VERSION 5.7 ;
  NOWIREEXTENSIONATPIN ON ;
  DIVIDERCHAR "/" ;
  BUSBITCHARS "[]" ;
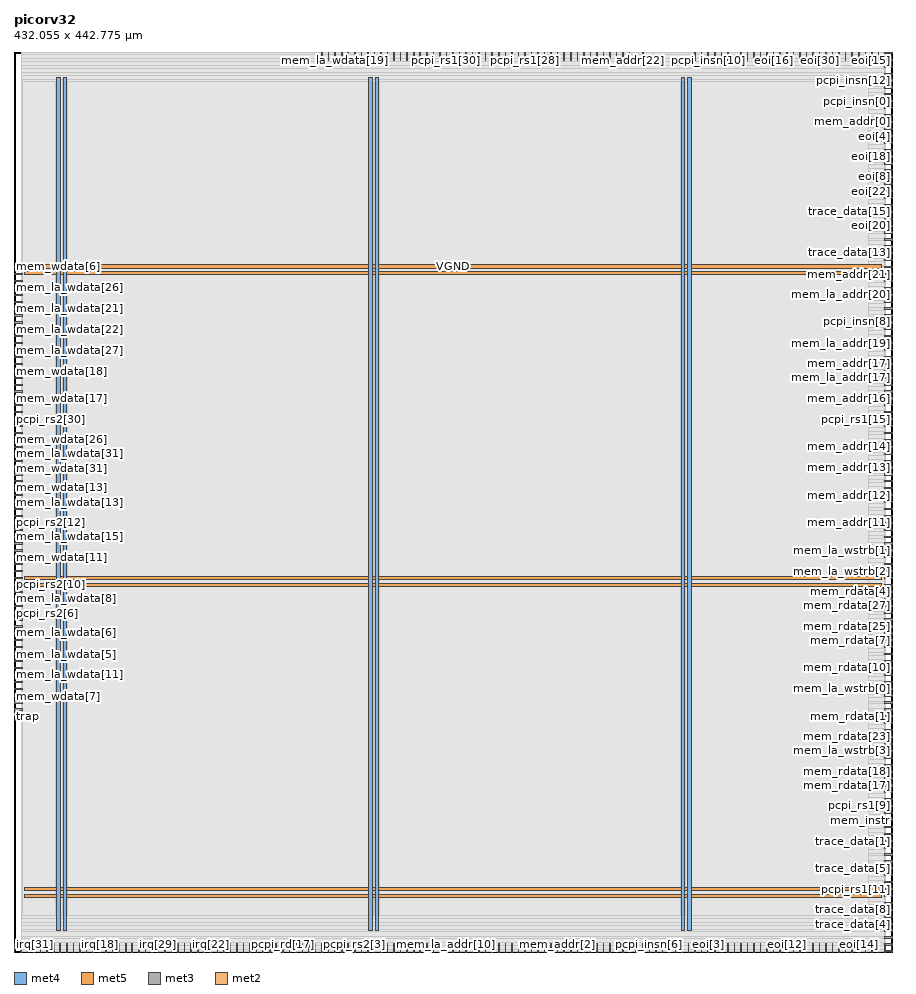
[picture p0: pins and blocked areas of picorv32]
MACRO picorv32
  CLASS BLOCK ;
  FOREIGN picorv32 ;
  ORIGIN 0.000 0.000 ;
  SIZE 432.055 BY 442.775 ;
  PIN VGND
    DIRECTION INOUT ;
    USE GROUND ;
    PORT
      LAYER met4 ;
        RECT 24.340 10.640 25.940 430.000 ;
    END
    PORT
      LAYER met4 ;
        RECT 177.940 10.640 179.540 430.000 ;
    END
    PORT
      LAYER met4 ;
        RECT 331.540 10.640 333.140 430.000 ;
    END
    PORT
      LAYER met5 ;
        RECT 5.280 30.030 426.660 31.630 ;
    END
    PORT
      LAYER met5 ;
        RECT 5.280 183.210 426.660 184.810 ;
    END
    PORT
      LAYER met5 ;
        RECT 5.280 336.390 426.660 337.990 ;
    END
  END VGND
  PIN VPWR
    DIRECTION INOUT ;
    USE POWER ;
    PORT
      LAYER met4 ;
        RECT 21.040 10.640 22.640 430.000 ;
    END
    PORT
      LAYER met4 ;
        RECT 174.640 10.640 176.240 430.000 ;
    END
    PORT
      LAYER met4 ;
        RECT 328.240 10.640 329.840 430.000 ;
    END
    PORT
      LAYER met5 ;
        RECT 5.280 26.730 426.660 28.330 ;
    END
    PORT
      LAYER met5 ;
        RECT 5.280 179.910 426.660 181.510 ;
    END
    PORT
      LAYER met5 ;
        RECT 5.280 333.090 426.660 334.690 ;
    END
  END VPWR
  PIN clk
    DIRECTION INPUT ;
    USE SIGNAL ;
    ANTENNAGATEAREA 0.990000 ;
    PORT
      LAYER met3 ;
        RECT 428.055 0.040 432.055 0.640 ;
    END
  END clk
  PIN eoi[0]
    DIRECTION OUTPUT ;
    USE SIGNAL ;
    PORT
      LAYER met2 ;
        RECT 283.450 0.000 283.730 4.000 ;
    END
  END eoi[0]
  PIN eoi[10]
    DIRECTION OUTPUT ;
    USE SIGNAL ;
    PORT
      LAYER met3 ;
        RECT 428.055 44.240 432.055 44.840 ;
    END
  END eoi[10]
  PIN eoi[11]
    DIRECTION OUTPUT ;
    USE SIGNAL ;
    PORT
      LAYER met3 ;
        RECT 428.055 3.440 432.055 4.040 ;
    END
  END eoi[11]
  PIN eoi[12]
    DIRECTION OUTPUT ;
    USE SIGNAL ;
    PORT
      LAYER met2 ;
        RECT 380.050 0.000 380.330 4.000 ;
    END
  END eoi[12]
  PIN eoi[13]
    DIRECTION OUTPUT ;
    USE SIGNAL ;
    PORT
      LAYER met3 ;
        RECT 428.055 353.640 432.055 354.240 ;
    END
  END eoi[13]
  PIN eoi[14]
    DIRECTION OUTPUT ;
    USE SIGNAL ;
    PORT
      LAYER met2 ;
        RECT 415.470 0.000 415.750 4.000 ;
    END
  END eoi[14]
  PIN eoi[15]
    DIRECTION OUTPUT ;
    USE SIGNAL ;
    PORT
      LAYER met2 ;
        RECT 428.350 438.775 428.630 442.775 ;
    END
  END eoi[15]
  PIN eoi[16]
    DIRECTION OUTPUT ;
    USE SIGNAL ;
    PORT
      LAYER met2 ;
        RECT 373.610 438.775 373.890 442.775 ;
    END
  END eoi[16]
  PIN eoi[17]
    DIRECTION OUTPUT ;
    USE SIGNAL ;
    PORT
      LAYER met3 ;
        RECT 428.055 363.840 432.055 364.440 ;
    END
  END eoi[17]
  PIN eoi[18]
    DIRECTION OUTPUT ;
    USE SIGNAL ;
    PORT
      LAYER met3 ;
        RECT 428.055 391.040 432.055 391.640 ;
    END
  END eoi[18]
  PIN eoi[19]
    DIRECTION OUTPUT ;
    USE SIGNAL ;
    PORT
      LAYER met3 ;
        RECT 428.055 421.640 432.055 422.240 ;
    END
  END eoi[19]
  PIN eoi[1]
    DIRECTION OUTPUT ;
    USE SIGNAL ;
    PORT
      LAYER met2 ;
        RECT 392.930 438.775 393.210 442.775 ;
    END
  END eoi[1]
  PIN eoi[20]
    DIRECTION OUTPUT ;
    USE SIGNAL ;
    PORT
      LAYER met3 ;
        RECT 428.055 357.040 432.055 357.640 ;
    END
  END eoi[20]
  PIN eoi[21]
    DIRECTION OUTPUT ;
    USE SIGNAL ;
    PORT
      LAYER met2 ;
        RECT 383.270 438.775 383.550 442.775 ;
    END
  END eoi[21]
  PIN eoi[22]
    DIRECTION OUTPUT ;
    USE SIGNAL ;
    PORT
      LAYER met3 ;
        RECT 428.055 374.040 432.055 374.640 ;
    END
  END eoi[22]
  PIN eoi[23]
    DIRECTION OUTPUT ;
    USE SIGNAL ;
    PORT
      LAYER met2 ;
        RECT 425.130 438.775 425.410 442.775 ;
    END
  END eoi[23]
  PIN eoi[24]
    DIRECTION OUTPUT ;
    USE SIGNAL ;
    PORT
      LAYER met3 ;
        RECT 428.055 51.040 432.055 51.640 ;
    END
  END eoi[24]
  PIN eoi[25]
    DIRECTION OUTPUT ;
    USE SIGNAL ;
    PORT
      LAYER met2 ;
        RECT 363.950 438.775 364.230 442.775 ;
    END
  END eoi[25]
  PIN eoi[26]
    DIRECTION OUTPUT ;
    USE SIGNAL ;
    PORT
      LAYER met2 ;
        RECT 415.470 438.775 415.750 442.775 ;
    END
  END eoi[26]
  PIN eoi[27]
    DIRECTION OUTPUT ;
    USE SIGNAL ;
    PORT
      LAYER met2 ;
        RECT 344.630 0.000 344.910 4.000 ;
    END
  END eoi[27]
  PIN eoi[28]
    DIRECTION OUTPUT ;
    USE SIGNAL ;
    PORT
      LAYER met2 ;
        RECT 418.690 438.775 418.970 442.775 ;
    END
  END eoi[28]
  PIN eoi[29]
    DIRECTION OUTPUT ;
    USE SIGNAL ;
    PORT
      LAYER met2 ;
        RECT 373.610 0.000 373.890 4.000 ;
    END
  END eoi[29]
  PIN eoi[2]
    DIRECTION OUTPUT ;
    USE SIGNAL ;
    PORT
      LAYER met2 ;
        RECT 402.590 438.775 402.870 442.775 ;
    END
  END eoi[2]
  PIN eoi[30]
    DIRECTION OUTPUT ;
    USE SIGNAL ;
    PORT
      LAYER met2 ;
        RECT 396.150 438.775 396.430 442.775 ;
    END
  END eoi[30]
  PIN eoi[31]
    DIRECTION OUTPUT ;
    USE SIGNAL ;
    PORT
      LAYER met2 ;
        RECT 370.390 438.775 370.670 442.775 ;
    END
  END eoi[31]
  PIN eoi[3]
    DIRECTION OUTPUT ;
    USE SIGNAL ;
    PORT
      LAYER met2 ;
        RECT 341.410 0.000 341.690 4.000 ;
    END
  END eoi[3]
  PIN eoi[4]
    DIRECTION OUTPUT ;
    USE SIGNAL ;
    PORT
      LAYER met3 ;
        RECT 428.055 404.640 432.055 405.240 ;
    END
  END eoi[4]
  PIN eoi[5]
    DIRECTION OUTPUT ;
    USE SIGNAL ;
    PORT
      LAYER met2 ;
        RECT 357.510 438.775 357.790 442.775 ;
    END
  END eoi[5]
  PIN eoi[6]
    DIRECTION OUTPUT ;
    USE SIGNAL ;
    PORT
      LAYER met3 ;
        RECT 428.055 23.840 432.055 24.440 ;
    END
  END eoi[6]
  PIN eoi[7]
    DIRECTION OUTPUT ;
    USE SIGNAL ;
    PORT
      LAYER met3 ;
        RECT 428.055 336.640 432.055 337.240 ;
    END
  END eoi[7]
  PIN eoi[8]
    DIRECTION OUTPUT ;
    USE SIGNAL ;
    PORT
      LAYER met3 ;
        RECT 428.055 377.440 432.055 378.040 ;
    END
  END eoi[8]
  PIN eoi[9]
    DIRECTION OUTPUT ;
    USE SIGNAL ;
    PORT
      LAYER met2 ;
        RECT 360.730 438.775 361.010 442.775 ;
    END
  END eoi[9]
  PIN irq[0]
    DIRECTION INPUT ;
    USE SIGNAL ;
    PORT
      LAYER met2 ;
        RECT 431.570 0.000 431.850 4.000 ;
    END
  END irq[0]
  PIN irq[10]
    DIRECTION INPUT ;
    USE SIGNAL ;
    PORT
      LAYER met2 ;
        RECT 116.010 0.000 116.290 4.000 ;
    END
  END irq[10]
  PIN irq[11]
    DIRECTION INPUT ;
    USE SIGNAL ;
    PORT
      LAYER met2 ;
        RECT 80.590 0.000 80.870 4.000 ;
    END
  END irq[11]
  PIN irq[12]
    DIRECTION INPUT ;
    USE SIGNAL ;
    PORT
      LAYER met2 ;
        RECT 74.150 0.000 74.430 4.000 ;
    END
  END irq[12]
  PIN irq[13]
    DIRECTION INPUT ;
    USE SIGNAL ;
    PORT
      LAYER met2 ;
        RECT 45.170 0.000 45.450 4.000 ;
    END
  END irq[13]
  PIN irq[14]
    DIRECTION INPUT ;
    USE SIGNAL ;
    PORT
      LAYER met2 ;
        RECT 64.490 0.000 64.770 4.000 ;
    END
  END irq[14]
  PIN irq[15]
    DIRECTION INPUT ;
    USE SIGNAL ;
    PORT
      LAYER met2 ;
        RECT 61.270 0.000 61.550 4.000 ;
    END
  END irq[15]
  PIN irq[16]
    DIRECTION INPUT ;
    USE SIGNAL ;
    PORT
      LAYER met2 ;
        RECT 138.550 0.000 138.830 4.000 ;
    END
  END irq[16]
  PIN irq[17]
    DIRECTION INPUT ;
    USE SIGNAL ;
    PORT
      LAYER met2 ;
        RECT 51.610 0.000 51.890 4.000 ;
    END
  END irq[17]
  PIN irq[18]
    DIRECTION INPUT ;
    USE SIGNAL ;
    PORT
      LAYER met2 ;
        RECT 41.950 0.000 42.230 4.000 ;
    END
  END irq[18]
  PIN irq[19]
    DIRECTION INPUT ;
    USE SIGNAL ;
    PORT
      LAYER met2 ;
        RECT 315.650 0.000 315.930 4.000 ;
    END
  END irq[19]
  PIN irq[1]
    DIRECTION INPUT ;
    USE SIGNAL ;
    PORT
      LAYER met2 ;
        RECT 135.330 0.000 135.610 4.000 ;
    END
  END irq[1]
  PIN irq[20]
    DIRECTION INPUT ;
    USE SIGNAL ;
    PORT
      LAYER met2 ;
        RECT 67.710 0.000 67.990 4.000 ;
    END
  END irq[20]
  PIN irq[21]
    DIRECTION INPUT ;
    USE SIGNAL ;
    PORT
      LAYER met2 ;
        RECT 22.630 0.000 22.910 4.000 ;
    END
  END irq[21]
  PIN irq[22]
    DIRECTION INPUT ;
    USE SIGNAL ;
    PORT
      LAYER met2 ;
        RECT 96.690 0.000 96.970 4.000 ;
    END
  END irq[22]
  PIN irq[23]
    DIRECTION INPUT ;
    USE SIGNAL ;
    PORT
      LAYER met2 ;
        RECT 77.370 0.000 77.650 4.000 ;
    END
  END irq[23]
  PIN irq[24]
    DIRECTION INPUT ;
    USE SIGNAL ;
    PORT
      LAYER met2 ;
        RECT 54.830 0.000 55.110 4.000 ;
    END
  END irq[24]
  PIN irq[25]
    DIRECTION INPUT ;
    USE SIGNAL ;
    PORT
      LAYER met2 ;
        RECT 421.910 0.000 422.190 4.000 ;
    END
  END irq[25]
  PIN irq[26]
    DIRECTION INPUT ;
    USE SIGNAL ;
    PORT
      LAYER met2 ;
        RECT 87.030 0.000 87.310 4.000 ;
    END
  END irq[26]
  PIN irq[27]
    DIRECTION INPUT ;
    USE SIGNAL ;
    PORT
      LAYER met2 ;
        RECT 119.230 0.000 119.510 4.000 ;
    END
  END irq[27]
  PIN irq[28]
    DIRECTION INPUT ;
    USE SIGNAL ;
    PORT
      LAYER met2 ;
        RECT 103.130 0.000 103.410 4.000 ;
    END
  END irq[28]
  PIN irq[29]
    DIRECTION INPUT ;
    USE SIGNAL ;
    PORT
      LAYER met2 ;
        RECT 70.930 0.000 71.210 4.000 ;
    END
  END irq[29]
  PIN irq[2]
    DIRECTION INPUT ;
    USE SIGNAL ;
    PORT
      LAYER met2 ;
        RECT 90.250 0.000 90.530 4.000 ;
    END
  END irq[2]
  PIN irq[30]
    DIRECTION INPUT ;
    USE SIGNAL ;
    PORT
      LAYER met2 ;
        RECT 289.890 0.000 290.170 4.000 ;
    END
  END irq[30]
  PIN irq[31]
    DIRECTION INPUT ;
    USE SIGNAL ;
    PORT
      LAYER met2 ;
        RECT 0.090 0.000 0.370 4.000 ;
    END
  END irq[31]
  PIN irq[3]
    DIRECTION INPUT ;
    USE SIGNAL ;
    PORT
      LAYER met2 ;
        RECT 409.030 0.000 409.310 4.000 ;
    END
  END irq[3]
  PIN irq[4]
    DIRECTION INPUT ;
    USE SIGNAL ;
    PORT
      LAYER met2 ;
        RECT 122.450 0.000 122.730 4.000 ;
    END
  END irq[4]
  PIN irq[5]
    DIRECTION INPUT ;
    USE SIGNAL ;
    PORT
      LAYER met2 ;
        RECT 106.350 0.000 106.630 4.000 ;
    END
  END irq[5]
  PIN irq[6]
    DIRECTION INPUT ;
    USE SIGNAL ;
    PORT
      LAYER met2 ;
        RECT 144.990 0.000 145.270 4.000 ;
    END
  END irq[6]
  PIN irq[7]
    DIRECTION INPUT ;
    USE SIGNAL ;
    PORT
      LAYER met2 ;
        RECT 112.790 0.000 113.070 4.000 ;
    END
  END irq[7]
  PIN irq[8]
    DIRECTION INPUT ;
    USE SIGNAL ;
    PORT
      LAYER met2 ;
        RECT 99.910 0.000 100.190 4.000 ;
    END
  END irq[8]
  PIN irq[9]
    DIRECTION INPUT ;
    USE SIGNAL ;
    PORT
      LAYER met2 ;
        RECT 93.470 0.000 93.750 4.000 ;
    END
  END irq[9]
  PIN mem_addr[0]
    DIRECTION OUTPUT ;
    USE SIGNAL ;
    PORT
      LAYER met3 ;
        RECT 428.055 408.040 432.055 408.640 ;
    END
  END mem_addr[0]
  PIN mem_addr[10]
    DIRECTION OUTPUT ;
    USE SIGNAL ;
    ANTENNADIFFAREA 0.340600 ;
    PORT
      LAYER met2 ;
        RECT 222.270 0.000 222.550 4.000 ;
    END
  END mem_addr[10]
  PIN mem_addr[11]
    DIRECTION OUTPUT ;
    USE SIGNAL ;
    ANTENNADIFFAREA 0.340600 ;
    PORT
      LAYER met3 ;
        RECT 428.055 210.840 432.055 211.440 ;
    END
  END mem_addr[11]
  PIN mem_addr[12]
    DIRECTION OUTPUT ;
    USE SIGNAL ;
    ANTENNADIFFAREA 0.340600 ;
    PORT
      LAYER met3 ;
        RECT 428.055 224.440 432.055 225.040 ;
    END
  END mem_addr[12]
  PIN mem_addr[13]
    DIRECTION OUTPUT ;
    USE SIGNAL ;
    ANTENNADIFFAREA 0.340600 ;
    PORT
      LAYER met3 ;
        RECT 428.055 238.040 432.055 238.640 ;
    END
  END mem_addr[13]
  PIN mem_addr[14]
    DIRECTION OUTPUT ;
    USE SIGNAL ;
    ANTENNADIFFAREA 0.340600 ;
    PORT
      LAYER met3 ;
        RECT 428.055 244.840 432.055 245.440 ;
    END
  END mem_addr[14]
  PIN mem_addr[15]
    DIRECTION OUTPUT ;
    USE SIGNAL ;
    ANTENNADIFFAREA 0.340600 ;
    PORT
      LAYER met3 ;
        RECT 428.055 261.840 432.055 262.440 ;
    END
  END mem_addr[15]
  PIN mem_addr[16]
    DIRECTION OUTPUT ;
    USE SIGNAL ;
    ANTENNADIFFAREA 0.340600 ;
    PORT
      LAYER met3 ;
        RECT 428.055 272.040 432.055 272.640 ;
    END
  END mem_addr[16]
  PIN mem_addr[17]
    DIRECTION OUTPUT ;
    USE SIGNAL ;
    ANTENNADIFFAREA 0.340600 ;
    PORT
      LAYER met3 ;
        RECT 428.055 285.640 432.055 286.240 ;
    END
  END mem_addr[17]
  PIN mem_addr[18]
    DIRECTION OUTPUT ;
    USE SIGNAL ;
    ANTENNADIFFAREA 0.340600 ;
    PORT
      LAYER met3 ;
        RECT 428.055 292.440 432.055 293.040 ;
    END
  END mem_addr[18]
  PIN mem_addr[19]
    DIRECTION OUTPUT ;
    USE SIGNAL ;
    ANTENNADIFFAREA 0.340600 ;
    PORT
      LAYER met3 ;
        RECT 428.055 295.840 432.055 296.440 ;
    END
  END mem_addr[19]
  PIN mem_addr[1]
    DIRECTION OUTPUT ;
    USE SIGNAL ;
    PORT
      LAYER met2 ;
        RECT 309.210 0.000 309.490 4.000 ;
    END
  END mem_addr[1]
  PIN mem_addr[20]
    DIRECTION OUTPUT ;
    USE SIGNAL ;
    ANTENNADIFFAREA 0.340600 ;
    PORT
      LAYER met3 ;
        RECT 428.055 329.840 432.055 330.440 ;
    END
  END mem_addr[20]
  PIN mem_addr[21]
    DIRECTION OUTPUT ;
    USE SIGNAL ;
    ANTENNADIFFAREA 0.340600 ;
    PORT
      LAYER met3 ;
        RECT 428.055 333.240 432.055 333.840 ;
    END
  END mem_addr[21]
  PIN mem_addr[22]
    DIRECTION OUTPUT ;
    USE SIGNAL ;
    ANTENNADIFFAREA 0.340600 ;
    PORT
      LAYER met2 ;
        RECT 299.550 438.775 299.830 442.775 ;
    END
  END mem_addr[22]
  PIN mem_addr[23]
    DIRECTION OUTPUT ;
    USE SIGNAL ;
    ANTENNADIFFAREA 0.340600 ;
    PORT
      LAYER met2 ;
        RECT 286.670 438.775 286.950 442.775 ;
    END
  END mem_addr[23]
  PIN mem_addr[24]
    DIRECTION OUTPUT ;
    USE SIGNAL ;
    ANTENNADIFFAREA 0.340600 ;
    PORT
      LAYER met2 ;
        RECT 277.010 438.775 277.290 442.775 ;
    END
  END mem_addr[24]
  PIN mem_addr[25]
    DIRECTION OUTPUT ;
    USE SIGNAL ;
    ANTENNADIFFAREA 0.340600 ;
    PORT
      LAYER met2 ;
        RECT 260.910 438.775 261.190 442.775 ;
    END
  END mem_addr[25]
  PIN mem_addr[26]
    DIRECTION OUTPUT ;
    USE SIGNAL ;
    ANTENNADIFFAREA 0.340600 ;
    PORT
      LAYER met2 ;
        RECT 257.690 438.775 257.970 442.775 ;
    END
  END mem_addr[26]
  PIN mem_addr[27]
    DIRECTION OUTPUT ;
    USE SIGNAL ;
    ANTENNADIFFAREA 0.340600 ;
    PORT
      LAYER met2 ;
        RECT 235.150 438.775 235.430 442.775 ;
    END
  END mem_addr[27]
  PIN mem_addr[28]
    DIRECTION OUTPUT ;
    USE SIGNAL ;
    ANTENNADIFFAREA 0.340600 ;
    PORT
      LAYER met2 ;
        RECT 222.270 438.775 222.550 442.775 ;
    END
  END mem_addr[28]
  PIN mem_addr[29]
    DIRECTION OUTPUT ;
    USE SIGNAL ;
    ANTENNADIFFAREA 0.340600 ;
    PORT
      LAYER met2 ;
        RECT 270.570 438.775 270.850 442.775 ;
    END
  END mem_addr[29]
  PIN mem_addr[2]
    DIRECTION OUTPUT ;
    USE SIGNAL ;
    ANTENNADIFFAREA 0.340600 ;
    PORT
      LAYER met2 ;
        RECT 267.350 0.000 267.630 4.000 ;
    END
  END mem_addr[2]
  PIN mem_addr[30]
    DIRECTION OUTPUT ;
    USE SIGNAL ;
    ANTENNADIFFAREA 0.340600 ;
    PORT
      LAYER met2 ;
        RECT 231.930 438.775 232.210 442.775 ;
    END
  END mem_addr[30]
  PIN mem_addr[31]
    DIRECTION OUTPUT ;
    USE SIGNAL ;
    ANTENNADIFFAREA 0.340600 ;
    PORT
      LAYER met2 ;
        RECT 244.810 438.775 245.090 442.775 ;
    END
  END mem_addr[31]
  PIN mem_addr[3]
    DIRECTION OUTPUT ;
    USE SIGNAL ;
    ANTENNADIFFAREA 0.340600 ;
    PORT
      LAYER met2 ;
        RECT 296.330 0.000 296.610 4.000 ;
    END
  END mem_addr[3]
  PIN mem_addr[4]
    DIRECTION OUTPUT ;
    USE SIGNAL ;
    ANTENNADIFFAREA 0.340600 ;
    PORT
      LAYER met2 ;
        RECT 251.250 0.000 251.530 4.000 ;
    END
  END mem_addr[4]
  PIN mem_addr[5]
    DIRECTION OUTPUT ;
    USE SIGNAL ;
    ANTENNADIFFAREA 0.340600 ;
    PORT
      LAYER met2 ;
        RECT 209.390 0.000 209.670 4.000 ;
    END
  END mem_addr[5]
  PIN mem_addr[6]
    DIRECTION OUTPUT ;
    USE SIGNAL ;
    ANTENNADIFFAREA 0.340600 ;
    PORT
      LAYER met2 ;
        RECT 238.370 0.000 238.650 4.000 ;
    END
  END mem_addr[6]
  PIN mem_addr[7]
    DIRECTION OUTPUT ;
    USE SIGNAL ;
    ANTENNADIFFAREA 0.340600 ;
    PORT
      LAYER met2 ;
        RECT 225.490 0.000 225.770 4.000 ;
    END
  END mem_addr[7]
  PIN mem_addr[8]
    DIRECTION OUTPUT ;
    USE SIGNAL ;
    ANTENNADIFFAREA 0.340600 ;
    PORT
      LAYER met2 ;
        RECT 228.710 0.000 228.990 4.000 ;
    END
  END mem_addr[8]
  PIN mem_addr[9]
    DIRECTION OUTPUT ;
    USE SIGNAL ;
    ANTENNADIFFAREA 0.340600 ;
    PORT
      LAYER met2 ;
        RECT 219.050 0.000 219.330 4.000 ;
    END
  END mem_addr[9]
  PIN mem_instr
    DIRECTION OUTPUT ;
    USE SIGNAL ;
    ANTENNADIFFAREA 0.340600 ;
    PORT
      LAYER met3 ;
        RECT 428.055 64.640 432.055 65.240 ;
    END
  END mem_instr
  PIN mem_la_addr[0]
    DIRECTION OUTPUT ;
    USE SIGNAL ;
    PORT
      LAYER met2 ;
        RECT 331.750 0.000 332.030 4.000 ;
    END
  END mem_la_addr[0]
  PIN mem_la_addr[10]
    DIRECTION OUTPUT ;
    USE SIGNAL ;
    ANTENNADIFFAREA 0.340600 ;
    PORT
      LAYER met2 ;
        RECT 212.610 0.000 212.890 4.000 ;
    END
  END mem_la_addr[10]
  PIN mem_la_addr[11]
    DIRECTION OUTPUT ;
    USE SIGNAL ;
    ANTENNADIFFAREA 0.340600 ;
    PORT
      LAYER met3 ;
        RECT 428.055 13.640 432.055 14.240 ;
    END
  END mem_la_addr[11]
  PIN mem_la_addr[12]
    DIRECTION OUTPUT ;
    USE SIGNAL ;
    ANTENNADIFFAREA 0.340600 ;
    PORT
      LAYER met3 ;
        RECT 428.055 221.040 432.055 221.640 ;
    END
  END mem_la_addr[12]
  PIN mem_la_addr[13]
    DIRECTION OUTPUT ;
    USE SIGNAL ;
    ANTENNADIFFAREA 0.340600 ;
    PORT
      LAYER met3 ;
        RECT 428.055 234.640 432.055 235.240 ;
    END
  END mem_la_addr[13]
  PIN mem_la_addr[14]
    DIRECTION OUTPUT ;
    USE SIGNAL ;
    ANTENNADIFFAREA 0.340600 ;
    PORT
      LAYER met3 ;
        RECT 428.055 241.440 432.055 242.040 ;
    END
  END mem_la_addr[14]
  PIN mem_la_addr[15]
    DIRECTION OUTPUT ;
    USE SIGNAL ;
    ANTENNADIFFAREA 0.340600 ;
    PORT
      LAYER met3 ;
        RECT 428.055 255.040 432.055 255.640 ;
    END
  END mem_la_addr[15]
  PIN mem_la_addr[16]
    DIRECTION OUTPUT ;
    USE SIGNAL ;
    ANTENNADIFFAREA 0.340600 ;
    PORT
      LAYER met3 ;
        RECT 428.055 268.640 432.055 269.240 ;
    END
  END mem_la_addr[16]
  PIN mem_la_addr[17]
    DIRECTION OUTPUT ;
    USE SIGNAL ;
    ANTENNADIFFAREA 0.340600 ;
    PORT
      LAYER met3 ;
        RECT 428.055 282.240 432.055 282.840 ;
    END
  END mem_la_addr[17]
  PIN mem_la_addr[18]
    DIRECTION OUTPUT ;
    USE SIGNAL ;
    ANTENNADIFFAREA 0.340600 ;
    PORT
      LAYER met3 ;
        RECT 428.055 302.640 432.055 303.240 ;
    END
  END mem_la_addr[18]
  PIN mem_la_addr[19]
    DIRECTION OUTPUT ;
    USE SIGNAL ;
    ANTENNADIFFAREA 0.340600 ;
    PORT
      LAYER met3 ;
        RECT 428.055 299.240 432.055 299.840 ;
    END
  END mem_la_addr[19]
  PIN mem_la_addr[1]
    DIRECTION OUTPUT ;
    USE SIGNAL ;
    PORT
      LAYER met3 ;
        RECT 428.055 47.640 432.055 48.240 ;
    END
  END mem_la_addr[1]
  PIN mem_la_addr[20]
    DIRECTION OUTPUT ;
    USE SIGNAL ;
    ANTENNADIFFAREA 0.340600 ;
    PORT
      LAYER met3 ;
        RECT 428.055 323.040 432.055 323.640 ;
    END
  END mem_la_addr[20]
  PIN mem_la_addr[21]
    DIRECTION OUTPUT ;
    USE SIGNAL ;
    ANTENNADIFFAREA 0.340600 ;
    PORT
      LAYER met3 ;
        RECT 428.055 309.440 432.055 310.040 ;
    END
  END mem_la_addr[21]
  PIN mem_la_addr[22]
    DIRECTION OUTPUT ;
    USE SIGNAL ;
    ANTENNADIFFAREA 0.340600 ;
    PORT
      LAYER met2 ;
        RECT 296.330 438.775 296.610 442.775 ;
    END
  END mem_la_addr[22]
  PIN mem_la_addr[23]
    DIRECTION OUTPUT ;
    USE SIGNAL ;
    ANTENNADIFFAREA 0.340600 ;
    PORT
      LAYER met2 ;
        RECT 283.450 438.775 283.730 442.775 ;
    END
  END mem_la_addr[23]
  PIN mem_la_addr[24]
    DIRECTION OUTPUT ;
    USE SIGNAL ;
    ANTENNADIFFAREA 0.340600 ;
    PORT
      LAYER met2 ;
        RECT 273.790 438.775 274.070 442.775 ;
    END
  END mem_la_addr[24]
  PIN mem_la_addr[25]
    DIRECTION OUTPUT ;
    USE SIGNAL ;
    ANTENNADIFFAREA 0.340600 ;
    PORT
      LAYER met2 ;
        RECT 264.130 438.775 264.410 442.775 ;
    END
  END mem_la_addr[25]
  PIN mem_la_addr[26]
    DIRECTION OUTPUT ;
    USE SIGNAL ;
    ANTENNADIFFAREA 0.340600 ;
    PORT
      LAYER met2 ;
        RECT 254.470 438.775 254.750 442.775 ;
    END
  END mem_la_addr[26]
  PIN mem_la_addr[27]
    DIRECTION OUTPUT ;
    USE SIGNAL ;
    ANTENNADIFFAREA 0.340600 ;
    PORT
      LAYER met2 ;
        RECT 238.370 438.775 238.650 442.775 ;
    END
  END mem_la_addr[27]
  PIN mem_la_addr[28]
    DIRECTION OUTPUT ;
    USE SIGNAL ;
    ANTENNADIFFAREA 0.340600 ;
    PORT
      LAYER met2 ;
        RECT 225.490 438.775 225.770 442.775 ;
    END
  END mem_la_addr[28]
  PIN mem_la_addr[29]
    DIRECTION OUTPUT ;
    USE SIGNAL ;
    ANTENNADIFFAREA 0.340600 ;
    PORT
      LAYER met2 ;
        RECT 267.350 438.775 267.630 442.775 ;
    END
  END mem_la_addr[29]
  PIN mem_la_addr[2]
    DIRECTION OUTPUT ;
    USE SIGNAL ;
    ANTENNADIFFAREA 0.340600 ;
    PORT
      LAYER met2 ;
        RECT 270.570 0.000 270.850 4.000 ;
    END
  END mem_la_addr[2]
  PIN mem_la_addr[30]
    DIRECTION OUTPUT ;
    USE SIGNAL ;
    ANTENNADIFFAREA 0.340600 ;
    PORT
      LAYER met2 ;
        RECT 228.710 438.775 228.990 442.775 ;
    END
  END mem_la_addr[30]
  PIN mem_la_addr[31]
    DIRECTION OUTPUT ;
    USE SIGNAL ;
    ANTENNADIFFAREA 0.340600 ;
    PORT
      LAYER met2 ;
        RECT 241.590 438.775 241.870 442.775 ;
    END
  END mem_la_addr[31]
  PIN mem_la_addr[3]
    DIRECTION OUTPUT ;
    USE SIGNAL ;
    ANTENNADIFFAREA 0.340600 ;
    PORT
      LAYER met2 ;
        RECT 293.110 0.000 293.390 4.000 ;
    END
  END mem_la_addr[3]
  PIN mem_la_addr[4]
    DIRECTION OUTPUT ;
    USE SIGNAL ;
    ANTENNADIFFAREA 0.340600 ;
    PORT
      LAYER met2 ;
        RECT 235.150 0.000 235.430 4.000 ;
    END
  END mem_la_addr[4]
  PIN mem_la_addr[5]
    DIRECTION OUTPUT ;
    USE SIGNAL ;
    ANTENNADIFFAREA 0.340600 ;
    PORT
      LAYER met2 ;
        RECT 231.930 0.000 232.210 4.000 ;
    END
  END mem_la_addr[5]
  PIN mem_la_addr[6]
    DIRECTION OUTPUT ;
    USE SIGNAL ;
    ANTENNADIFFAREA 0.340600 ;
    PORT
      LAYER met2 ;
        RECT 241.590 0.000 241.870 4.000 ;
    END
  END mem_la_addr[6]
  PIN mem_la_addr[7]
    DIRECTION OUTPUT ;
    USE SIGNAL ;
    ANTENNADIFFAREA 0.340600 ;
    PORT
      LAYER met2 ;
        RECT 244.810 0.000 245.090 4.000 ;
    END
  END mem_la_addr[7]
  PIN mem_la_addr[8]
    DIRECTION OUTPUT ;
    USE SIGNAL ;
    ANTENNADIFFAREA 0.340600 ;
    PORT
      LAYER met2 ;
        RECT 248.030 0.000 248.310 4.000 ;
    END
  END mem_la_addr[8]
  PIN mem_la_addr[9]
    DIRECTION OUTPUT ;
    USE SIGNAL ;
    ANTENNADIFFAREA 0.340600 ;
    PORT
      LAYER met2 ;
        RECT 215.830 0.000 216.110 4.000 ;
    END
  END mem_la_addr[9]
  PIN mem_la_read
    DIRECTION OUTPUT ;
    USE SIGNAL ;
    ANTENNADIFFAREA 0.340600 ;
    PORT
      LAYER met3 ;
        RECT 428.055 122.440 432.055 123.040 ;
    END
  END mem_la_read
  PIN mem_la_wdata[0]
    DIRECTION OUTPUT ;
    USE SIGNAL ;
    ANTENNADIFFAREA 0.340600 ;
    PORT
      LAYER met2 ;
        RECT 206.170 0.000 206.450 4.000 ;
    END
  END mem_la_wdata[0]
  PIN mem_la_wdata[10]
    DIRECTION OUTPUT ;
    USE SIGNAL ;
    ANTENNADIFFAREA 0.340600 ;
    PORT
      LAYER met3 ;
        RECT 0.000 122.440 4.000 123.040 ;
    END
  END mem_la_wdata[10]
  PIN mem_la_wdata[11]
    DIRECTION OUTPUT ;
    USE SIGNAL ;
    ANTENNADIFFAREA 0.340600 ;
    PORT
      LAYER met3 ;
        RECT 0.000 136.040 4.000 136.640 ;
    END
  END mem_la_wdata[11]
  PIN mem_la_wdata[12]
    DIRECTION OUTPUT ;
    USE SIGNAL ;
    ANTENNADIFFAREA 0.340600 ;
    PORT
      LAYER met3 ;
        RECT 0.000 166.640 4.000 167.240 ;
    END
  END mem_la_wdata[12]
  PIN mem_la_wdata[13]
    DIRECTION OUTPUT ;
    USE SIGNAL ;
    ANTENNADIFFAREA 0.340600 ;
    PORT
      LAYER met3 ;
        RECT 0.000 221.040 4.000 221.640 ;
    END
  END mem_la_wdata[13]
  PIN mem_la_wdata[14]
    DIRECTION OUTPUT ;
    USE SIGNAL ;
    ANTENNADIFFAREA 0.340600 ;
    PORT
      LAYER met3 ;
        RECT 0.000 217.640 4.000 218.240 ;
    END
  END mem_la_wdata[14]
  PIN mem_la_wdata[15]
    DIRECTION OUTPUT ;
    USE SIGNAL ;
    ANTENNADIFFAREA 0.340600 ;
    PORT
      LAYER met3 ;
        RECT 0.000 204.040 4.000 204.640 ;
    END
  END mem_la_wdata[15]
  PIN mem_la_wdata[16]
    DIRECTION OUTPUT ;
    USE SIGNAL ;
    ANTENNADIFFAREA 0.340600 ;
    PORT
      LAYER met2 ;
        RECT 186.850 438.775 187.130 442.775 ;
    END
  END mem_la_wdata[16]
  PIN mem_la_wdata[17]
    DIRECTION OUTPUT ;
    USE SIGNAL ;
    ANTENNADIFFAREA 0.340600 ;
    PORT
      LAYER met3 ;
        RECT 0.000 336.640 4.000 337.240 ;
    END
  END mem_la_wdata[17]
  PIN mem_la_wdata[18]
    DIRECTION OUTPUT ;
    USE SIGNAL ;
    ANTENNADIFFAREA 0.340600 ;
    PORT
      LAYER met3 ;
        RECT 0.000 295.840 4.000 296.440 ;
    END
  END mem_la_wdata[18]
  PIN mem_la_wdata[19]
    DIRECTION OUTPUT ;
    USE SIGNAL ;
    ANTENNADIFFAREA 0.340600 ;
    PORT
      LAYER met2 ;
        RECT 157.870 438.775 158.150 442.775 ;
    END
  END mem_la_wdata[19]
  PIN mem_la_wdata[1]
    DIRECTION OUTPUT ;
    USE SIGNAL ;
    ANTENNADIFFAREA 0.340600 ;
    PORT
      LAYER met2 ;
        RECT 180.410 0.000 180.690 4.000 ;
    END
  END mem_la_wdata[1]
  PIN mem_la_wdata[20]
    DIRECTION OUTPUT ;
    USE SIGNAL ;
    ANTENNADIFFAREA 0.340600 ;
    PORT
      LAYER met2 ;
        RECT 202.950 438.775 203.230 442.775 ;
    END
  END mem_la_wdata[20]
  PIN mem_la_wdata[21]
    DIRECTION OUTPUT ;
    USE SIGNAL ;
    ANTENNADIFFAREA 0.340600 ;
    PORT
      LAYER met3 ;
        RECT 0.000 316.240 4.000 316.840 ;
    END
  END mem_la_wdata[21]
  PIN mem_la_wdata[22]
    DIRECTION OUTPUT ;
    USE SIGNAL ;
    ANTENNADIFFAREA 0.340600 ;
    PORT
      LAYER met3 ;
        RECT 0.000 306.040 4.000 306.640 ;
    END
  END mem_la_wdata[22]
  PIN mem_la_wdata[23]
    DIRECTION OUTPUT ;
    USE SIGNAL ;
    ANTENNADIFFAREA 0.340600 ;
    PORT
      LAYER met3 ;
        RECT 0.000 251.640 4.000 252.240 ;
    END
  END mem_la_wdata[23]
  PIN mem_la_wdata[24]
    DIRECTION OUTPUT ;
    USE SIGNAL ;
    ANTENNADIFFAREA 0.340600 ;
    PORT
      LAYER met2 ;
        RECT 164.310 438.775 164.590 442.775 ;
    END
  END mem_la_wdata[24]
  PIN mem_la_wdata[25]
    DIRECTION OUTPUT ;
    USE SIGNAL ;
    ANTENNADIFFAREA 0.340600 ;
    PORT
      LAYER met3 ;
        RECT 0.000 285.640 4.000 286.240 ;
    END
  END mem_la_wdata[25]
  PIN mem_la_wdata[26]
    DIRECTION OUTPUT ;
    USE SIGNAL ;
    ANTENNADIFFAREA 0.340600 ;
    PORT
      LAYER met3 ;
        RECT 0.000 323.040 4.000 323.640 ;
    END
  END mem_la_wdata[26]
  PIN mem_la_wdata[27]
    DIRECTION OUTPUT ;
    USE SIGNAL ;
    ANTENNADIFFAREA 0.340600 ;
    PORT
      LAYER met3 ;
        RECT 0.000 299.240 4.000 299.840 ;
    END
  END mem_la_wdata[27]
  PIN mem_la_wdata[28]
    DIRECTION OUTPUT ;
    USE SIGNAL ;
    ANTENNADIFFAREA 0.340600 ;
    PORT
      LAYER met3 ;
        RECT 0.000 275.440 4.000 276.040 ;
    END
  END mem_la_wdata[28]
  PIN mem_la_wdata[29]
    DIRECTION OUTPUT ;
    USE SIGNAL ;
    ANTENNADIFFAREA 0.340600 ;
    PORT
      LAYER met3 ;
        RECT 0.000 268.640 4.000 269.240 ;
    END
  END mem_la_wdata[29]
  PIN mem_la_wdata[2]
    DIRECTION OUTPUT ;
    USE SIGNAL ;
    ANTENNADIFFAREA 0.340600 ;
    PORT
      LAYER met2 ;
        RECT 199.730 0.000 200.010 4.000 ;
    END
  END mem_la_wdata[2]
  PIN mem_la_wdata[30]
    DIRECTION OUTPUT ;
    USE SIGNAL ;
    ANTENNADIFFAREA 0.340600 ;
    PORT
      LAYER met3 ;
        RECT 0.000 329.840 4.000 330.440 ;
    END
  END mem_la_wdata[30]
  PIN mem_la_wdata[31]
    DIRECTION OUTPUT ;
    USE SIGNAL ;
    ANTENNADIFFAREA 0.340600 ;
    PORT
      LAYER met3 ;
        RECT 0.000 244.840 4.000 245.440 ;
    END
  END mem_la_wdata[31]
  PIN mem_la_wdata[3]
    DIRECTION OUTPUT ;
    USE SIGNAL ;
    ANTENNADIFFAREA 0.340600 ;
    PORT
      LAYER met2 ;
        RECT 186.850 0.000 187.130 4.000 ;
    END
  END mem_la_wdata[3]
  PIN mem_la_wdata[4]
    DIRECTION OUTPUT ;
    USE SIGNAL ;
    ANTENNADIFFAREA 0.340600 ;
    PORT
      LAYER met2 ;
        RECT 196.510 0.000 196.790 4.000 ;
    END
  END mem_la_wdata[4]
  PIN mem_la_wdata[5]
    DIRECTION OUTPUT ;
    USE SIGNAL ;
    ANTENNADIFFAREA 0.340600 ;
    PORT
      LAYER met3 ;
        RECT 0.000 146.240 4.000 146.840 ;
    END
  END mem_la_wdata[5]
  PIN mem_la_wdata[6]
    DIRECTION OUTPUT ;
    USE SIGNAL ;
    ANTENNADIFFAREA 0.340600 ;
    PORT
      LAYER met3 ;
        RECT 0.000 153.040 4.000 153.640 ;
    END
  END mem_la_wdata[6]
  PIN mem_la_wdata[7]
    DIRECTION OUTPUT ;
    USE SIGNAL ;
    ANTENNADIFFAREA 0.340600 ;
    PORT
      LAYER met3 ;
        RECT 0.000 156.440 4.000 157.040 ;
    END
  END mem_la_wdata[7]
  PIN mem_la_wdata[8]
    DIRECTION OUTPUT ;
    USE SIGNAL ;
    ANTENNADIFFAREA 0.340600 ;
    PORT
      LAYER met3 ;
        RECT 0.000 173.440 4.000 174.040 ;
    END
  END mem_la_wdata[8]
  PIN mem_la_wdata[9]
    DIRECTION OUTPUT ;
    USE SIGNAL ;
    ANTENNADIFFAREA 0.340600 ;
    PORT
      LAYER met3 ;
        RECT 0.000 163.240 4.000 163.840 ;
    END
  END mem_la_wdata[9]
  PIN mem_la_write
    DIRECTION OUTPUT ;
    USE SIGNAL ;
    ANTENNADIFFAREA 0.340600 ;
    PORT
      LAYER met3 ;
        RECT 428.055 112.240 432.055 112.840 ;
    END
  END mem_la_write
  PIN mem_la_wstrb[0]
    DIRECTION OUTPUT ;
    USE SIGNAL ;
    ANTENNADIFFAREA 0.340600 ;
    PORT
      LAYER met3 ;
        RECT 428.055 129.240 432.055 129.840 ;
    END
  END mem_la_wstrb[0]
  PIN mem_la_wstrb[1]
    DIRECTION OUTPUT ;
    USE SIGNAL ;
    ANTENNADIFFAREA 0.340600 ;
    PORT
      LAYER met3 ;
        RECT 428.055 197.240 432.055 197.840 ;
    END
  END mem_la_wstrb[1]
  PIN mem_la_wstrb[2]
    DIRECTION OUTPUT ;
    USE SIGNAL ;
    ANTENNADIFFAREA 0.340600 ;
    PORT
      LAYER met3 ;
        RECT 428.055 187.040 432.055 187.640 ;
    END
  END mem_la_wstrb[2]
  PIN mem_la_wstrb[3]
    DIRECTION OUTPUT ;
    USE SIGNAL ;
    ANTENNADIFFAREA 0.340600 ;
    PORT
      LAYER met3 ;
        RECT 428.055 98.640 432.055 99.240 ;
    END
  END mem_la_wstrb[3]
  PIN mem_rdata[0]
    DIRECTION INPUT ;
    USE SIGNAL ;
    ANTENNAGATEAREA 0.196500 ;
    PORT
      LAYER met3 ;
        RECT 428.055 183.640 432.055 184.240 ;
    END
  END mem_rdata[0]
  PIN mem_rdata[10]
    DIRECTION INPUT ;
    USE SIGNAL ;
    ANTENNAGATEAREA 0.126000 ;
    PORT
      LAYER met3 ;
        RECT 428.055 136.040 432.055 136.640 ;
    END
  END mem_rdata[10]
  PIN mem_rdata[11]
    DIRECTION INPUT ;
    USE SIGNAL ;
    ANTENNAGATEAREA 0.126000 ;
    PORT
      LAYER met3 ;
        RECT 428.055 132.640 432.055 133.240 ;
    END
  END mem_rdata[11]
  PIN mem_rdata[12]
    DIRECTION INPUT ;
    USE SIGNAL ;
    ANTENNAGATEAREA 0.196500 ;
    PORT
      LAYER met3 ;
        RECT 428.055 207.440 432.055 208.040 ;
    END
  END mem_rdata[12]
  PIN mem_rdata[13]
    DIRECTION INPUT ;
    USE SIGNAL ;
    ANTENNAGATEAREA 0.196500 ;
    PORT
      LAYER met3 ;
        RECT 428.055 214.240 432.055 214.840 ;
    END
  END mem_rdata[13]
  PIN mem_rdata[14]
    DIRECTION INPUT ;
    USE SIGNAL ;
    ANTENNAGATEAREA 0.196500 ;
    PORT
      LAYER met3 ;
        RECT 428.055 217.640 432.055 218.240 ;
    END
  END mem_rdata[14]
  PIN mem_rdata[15]
    DIRECTION INPUT ;
    USE SIGNAL ;
    ANTENNAGATEAREA 0.196500 ;
    PORT
      LAYER met3 ;
        RECT 428.055 231.240 432.055 231.840 ;
    END
  END mem_rdata[15]
  PIN mem_rdata[16]
    DIRECTION INPUT ;
    USE SIGNAL ;
    ANTENNAGATEAREA 0.159000 ;
    PORT
      LAYER met3 ;
        RECT 428.055 61.240 432.055 61.840 ;
    END
  END mem_rdata[16]
  PIN mem_rdata[17]
    DIRECTION INPUT ;
    USE SIGNAL ;
    ANTENNAGATEAREA 0.159000 ;
    PORT
      LAYER met3 ;
        RECT 428.055 81.640 432.055 82.240 ;
    END
  END mem_rdata[17]
  PIN mem_rdata[18]
    DIRECTION INPUT ;
    USE SIGNAL ;
    ANTENNAGATEAREA 0.213000 ;
    PORT
      LAYER met3 ;
        RECT 428.055 85.040 432.055 85.640 ;
    END
  END mem_rdata[18]
  PIN mem_rdata[19]
    DIRECTION INPUT ;
    USE SIGNAL ;
    ANTENNAGATEAREA 0.159000 ;
    PORT
      LAYER met3 ;
        RECT 428.055 91.840 432.055 92.440 ;
    END
  END mem_rdata[19]
  PIN mem_rdata[1]
    DIRECTION INPUT ;
    USE SIGNAL ;
    ANTENNAGATEAREA 0.126000 ;
    PORT
      LAYER met3 ;
        RECT 428.055 115.640 432.055 116.240 ;
    END
  END mem_rdata[1]
  PIN mem_rdata[20]
    DIRECTION INPUT ;
    USE SIGNAL ;
    ANTENNAGATEAREA 0.213000 ;
    PORT
      LAYER met3 ;
        RECT 428.055 108.840 432.055 109.440 ;
    END
  END mem_rdata[20]
  PIN mem_rdata[21]
    DIRECTION INPUT ;
    USE SIGNAL ;
    ANTENNAGATEAREA 0.159000 ;
    PORT
      LAYER met3 ;
        RECT 428.055 119.040 432.055 119.640 ;
    END
  END mem_rdata[21]
  PIN mem_rdata[22]
    DIRECTION INPUT ;
    USE SIGNAL ;
    ANTENNAGATEAREA 0.159000 ;
    PORT
      LAYER met3 ;
        RECT 428.055 149.640 432.055 150.240 ;
    END
  END mem_rdata[22]
  PIN mem_rdata[23]
    DIRECTION INPUT ;
    USE SIGNAL ;
    ANTENNAGATEAREA 0.159000 ;
    PORT
      LAYER met3 ;
        RECT 428.055 102.040 432.055 102.640 ;
    END
  END mem_rdata[23]
  PIN mem_rdata[24]
    DIRECTION INPUT ;
    USE SIGNAL ;
    ANTENNAGATEAREA 0.159000 ;
    PORT
      LAYER met3 ;
        RECT 428.055 105.440 432.055 106.040 ;
    END
  END mem_rdata[24]
  PIN mem_rdata[25]
    DIRECTION INPUT ;
    USE SIGNAL ;
    ANTENNAGATEAREA 0.159000 ;
    PORT
      LAYER met3 ;
        RECT 428.055 159.840 432.055 160.440 ;
    END
  END mem_rdata[25]
  PIN mem_rdata[26]
    DIRECTION INPUT ;
    USE SIGNAL ;
    ANTENNAGATEAREA 0.159000 ;
    PORT
      LAYER met3 ;
        RECT 428.055 125.840 432.055 126.440 ;
    END
  END mem_rdata[26]
  PIN mem_rdata[27]
    DIRECTION INPUT ;
    USE SIGNAL ;
    ANTENNAGATEAREA 0.213000 ;
    PORT
      LAYER met3 ;
        RECT 428.055 170.040 432.055 170.640 ;
    END
  END mem_rdata[27]
  PIN mem_rdata[28]
    DIRECTION INPUT ;
    USE SIGNAL ;
    ANTENNAGATEAREA 0.159000 ;
    PORT
      LAYER met3 ;
        RECT 428.055 193.840 432.055 194.440 ;
    END
  END mem_rdata[28]
  PIN mem_rdata[29]
    DIRECTION INPUT ;
    USE SIGNAL ;
    ANTENNAGATEAREA 0.159000 ;
    PORT
      LAYER met3 ;
        RECT 428.055 258.440 432.055 259.040 ;
    END
  END mem_rdata[29]
  PIN mem_rdata[2]
    DIRECTION INPUT ;
    USE SIGNAL ;
    ANTENNAGATEAREA 0.196500 ;
    PORT
      LAYER met3 ;
        RECT 428.055 190.440 432.055 191.040 ;
    END
  END mem_rdata[2]
  PIN mem_rdata[30]
    DIRECTION INPUT ;
    USE SIGNAL ;
    ANTENNAGATEAREA 0.159000 ;
    PORT
      LAYER met3 ;
        RECT 428.055 251.640 432.055 252.240 ;
    END
  END mem_rdata[30]
  PIN mem_rdata[31]
    DIRECTION INPUT ;
    USE SIGNAL ;
    ANTENNAGATEAREA 0.126000 ;
    PORT
      LAYER met3 ;
        RECT 428.055 227.840 432.055 228.440 ;
    END
  END mem_rdata[31]
  PIN mem_rdata[3]
    DIRECTION INPUT ;
    USE SIGNAL ;
    ANTENNAGATEAREA 0.196500 ;
    PORT
      LAYER met3 ;
        RECT 428.055 180.240 432.055 180.840 ;
    END
  END mem_rdata[3]
  PIN mem_rdata[4]
    DIRECTION INPUT ;
    USE SIGNAL ;
    ANTENNAGATEAREA 0.196500 ;
    PORT
      LAYER met3 ;
        RECT 428.055 173.440 432.055 174.040 ;
    END
  END mem_rdata[4]
  PIN mem_rdata[5]
    DIRECTION INPUT ;
    USE SIGNAL ;
    ANTENNAGATEAREA 0.196500 ;
    PORT
      LAYER met3 ;
        RECT 428.055 163.240 432.055 163.840 ;
    END
  END mem_rdata[5]
  PIN mem_rdata[6]
    DIRECTION INPUT ;
    USE SIGNAL ;
    ANTENNAGATEAREA 0.196500 ;
    PORT
      LAYER met3 ;
        RECT 428.055 176.840 432.055 177.440 ;
    END
  END mem_rdata[6]
  PIN mem_rdata[7]
    DIRECTION INPUT ;
    USE SIGNAL ;
    ANTENNAGATEAREA 0.196500 ;
    PORT
      LAYER met3 ;
        RECT 428.055 156.440 432.055 157.040 ;
    END
  END mem_rdata[7]
  PIN mem_rdata[8]
    DIRECTION INPUT ;
    USE SIGNAL ;
    ANTENNAGATEAREA 0.126000 ;
    PORT
      LAYER met3 ;
        RECT 428.055 139.440 432.055 140.040 ;
    END
  END mem_rdata[8]
  PIN mem_rdata[9]
    DIRECTION INPUT ;
    USE SIGNAL ;
    ANTENNAGATEAREA 0.126000 ;
    PORT
      LAYER met3 ;
        RECT 428.055 142.840 432.055 143.440 ;
    END
  END mem_rdata[9]
  PIN mem_ready
    DIRECTION INPUT ;
    USE SIGNAL ;
    ANTENNAGATEAREA 0.126000 ;
    PORT
      LAYER met3 ;
        RECT 428.055 153.040 432.055 153.640 ;
    END
  END mem_ready
  PIN mem_valid
    DIRECTION OUTPUT ;
    USE SIGNAL ;
    ANTENNADIFFAREA 0.340600 ;
    PORT
      LAYER met3 ;
        RECT 428.055 146.240 432.055 146.840 ;
    END
  END mem_valid
  PIN mem_wdata[0]
    DIRECTION OUTPUT ;
    USE SIGNAL ;
    ANTENNADIFFAREA 0.340600 ;
    PORT
      LAYER met3 ;
        RECT 0.000 255.040 4.000 255.640 ;
    END
  END mem_wdata[0]
  PIN mem_wdata[10]
    DIRECTION OUTPUT ;
    USE SIGNAL ;
    ANTENNADIFFAREA 0.340600 ;
    PORT
      LAYER met3 ;
        RECT 0.000 200.640 4.000 201.240 ;
    END
  END mem_wdata[10]
  PIN mem_wdata[11]
    DIRECTION OUTPUT ;
    USE SIGNAL ;
    ANTENNADIFFAREA 0.340600 ;
    PORT
      LAYER met3 ;
        RECT 0.000 197.240 4.000 197.840 ;
    END
  END mem_wdata[11]
  PIN mem_wdata[12]
    DIRECTION OUTPUT ;
    USE SIGNAL ;
    ANTENNADIFFAREA 0.340600 ;
    PORT
      LAYER met3 ;
        RECT 0.000 183.640 4.000 184.240 ;
    END
  END mem_wdata[12]
  PIN mem_wdata[13]
    DIRECTION OUTPUT ;
    USE SIGNAL ;
    ANTENNADIFFAREA 0.340600 ;
    PORT
      LAYER met3 ;
        RECT 0.000 224.440 4.000 225.040 ;
    END
  END mem_wdata[13]
  PIN mem_wdata[14]
    DIRECTION OUTPUT ;
    USE SIGNAL ;
    ANTENNADIFFAREA 0.340600 ;
    PORT
      LAYER met3 ;
        RECT 0.000 214.240 4.000 214.840 ;
    END
  END mem_wdata[14]
  PIN mem_wdata[15]
    DIRECTION OUTPUT ;
    USE SIGNAL ;
    ANTENNADIFFAREA 0.340600 ;
    PORT
      LAYER met3 ;
        RECT 0.000 190.440 4.000 191.040 ;
    END
  END mem_wdata[15]
  PIN mem_wdata[16]
    DIRECTION OUTPUT ;
    USE SIGNAL ;
    ANTENNADIFFAREA 0.340600 ;
    PORT
      LAYER met3 ;
        RECT 0.000 309.440 4.000 310.040 ;
    END
  END mem_wdata[16]
  PIN mem_wdata[17]
    DIRECTION OUTPUT ;
    USE SIGNAL ;
    ANTENNADIFFAREA 0.340600 ;
    PORT
      LAYER met3 ;
        RECT 0.000 272.040 4.000 272.640 ;
    END
  END mem_wdata[17]
  PIN mem_wdata[18]
    DIRECTION OUTPUT ;
    USE SIGNAL ;
    ANTENNADIFFAREA 0.340600 ;
    PORT
      LAYER met3 ;
        RECT 0.000 289.040 4.000 289.640 ;
    END
  END mem_wdata[18]
  PIN mem_wdata[19]
    DIRECTION OUTPUT ;
    USE SIGNAL ;
    ANTENNADIFFAREA 0.340600 ;
    PORT
      LAYER met2 ;
        RECT 161.090 438.775 161.370 442.775 ;
    END
  END mem_wdata[19]
  PIN mem_wdata[1]
    DIRECTION OUTPUT ;
    USE SIGNAL ;
    ANTENNADIFFAREA 0.340600 ;
    PORT
      LAYER met3 ;
        RECT 0.000 159.840 4.000 160.440 ;
    END
  END mem_wdata[1]
  PIN mem_wdata[20]
    DIRECTION OUTPUT ;
    USE SIGNAL ;
    ANTENNADIFFAREA 0.340600 ;
    PORT
      LAYER met2 ;
        RECT 199.730 438.775 200.010 442.775 ;
    END
  END mem_wdata[20]
  PIN mem_wdata[21]
    DIRECTION OUTPUT ;
    USE SIGNAL ;
    ANTENNADIFFAREA 0.340600 ;
    PORT
      LAYER met3 ;
        RECT 0.000 319.640 4.000 320.240 ;
    END
  END mem_wdata[21]
  PIN mem_wdata[22]
    DIRECTION OUTPUT ;
    USE SIGNAL ;
    ANTENNADIFFAREA 0.340600 ;
    PORT
      LAYER met3 ;
        RECT 0.000 261.840 4.000 262.440 ;
    END
  END mem_wdata[22]
  PIN mem_wdata[23]
    DIRECTION OUTPUT ;
    USE SIGNAL ;
    ANTENNADIFFAREA 0.340600 ;
    PORT
      LAYER met3 ;
        RECT 0.000 312.840 4.000 313.440 ;
    END
  END mem_wdata[23]
  PIN mem_wdata[24]
    DIRECTION OUTPUT ;
    USE SIGNAL ;
    ANTENNADIFFAREA 0.340600 ;
    PORT
      LAYER met2 ;
        RECT 167.530 438.775 167.810 442.775 ;
    END
  END mem_wdata[24]
  PIN mem_wdata[25]
    DIRECTION OUTPUT ;
    USE SIGNAL ;
    ANTENNADIFFAREA 0.340600 ;
    PORT
      LAYER met3 ;
        RECT 0.000 278.840 4.000 279.440 ;
    END
  END mem_wdata[25]
  PIN mem_wdata[26]
    DIRECTION OUTPUT ;
    USE SIGNAL ;
    ANTENNADIFFAREA 0.340600 ;
    PORT
      LAYER met3 ;
        RECT 0.000 248.240 4.000 248.840 ;
    END
  END mem_wdata[26]
  PIN mem_wdata[27]
    DIRECTION OUTPUT ;
    USE SIGNAL ;
    ANTENNADIFFAREA 0.340600 ;
    PORT
      LAYER met3 ;
        RECT 0.000 302.640 4.000 303.240 ;
    END
  END mem_wdata[27]
  PIN mem_wdata[28]
    DIRECTION OUTPUT ;
    USE SIGNAL ;
    ANTENNADIFFAREA 0.340600 ;
    PORT
      LAYER met3 ;
        RECT 0.000 282.240 4.000 282.840 ;
    END
  END mem_wdata[28]
  PIN mem_wdata[29]
    DIRECTION OUTPUT ;
    USE SIGNAL ;
    ANTENNADIFFAREA 0.340600 ;
    PORT
      LAYER met3 ;
        RECT 0.000 258.440 4.000 259.040 ;
    END
  END mem_wdata[29]
  PIN mem_wdata[2]
    DIRECTION OUTPUT ;
    USE SIGNAL ;
    ANTENNADIFFAREA 0.340600 ;
    PORT
      LAYER met3 ;
        RECT 0.000 142.840 4.000 143.440 ;
    END
  END mem_wdata[2]
  PIN mem_wdata[30]
    DIRECTION OUTPUT ;
    USE SIGNAL ;
    ANTENNADIFFAREA 0.340600 ;
    PORT
      LAYER met3 ;
        RECT 0.000 326.440 4.000 327.040 ;
    END
  END mem_wdata[30]
  PIN mem_wdata[31]
    DIRECTION OUTPUT ;
    USE SIGNAL ;
    ANTENNADIFFAREA 0.340600 ;
    PORT
      LAYER met3 ;
        RECT 0.000 241.440 4.000 242.040 ;
    END
  END mem_wdata[31]
  PIN mem_wdata[3]
    DIRECTION OUTPUT ;
    USE SIGNAL ;
    ANTENNADIFFAREA 0.340600 ;
    PORT
      LAYER met3 ;
        RECT 0.000 132.640 4.000 133.240 ;
    END
  END mem_wdata[3]
  PIN mem_wdata[4]
    DIRECTION OUTPUT ;
    USE SIGNAL ;
    ANTENNADIFFAREA 0.340600 ;
    PORT
      LAYER met2 ;
        RECT 157.870 0.000 158.150 4.000 ;
    END
  END mem_wdata[4]
  PIN mem_wdata[5]
    DIRECTION OUTPUT ;
    USE SIGNAL ;
    ANTENNADIFFAREA 0.340600 ;
    PORT
      LAYER met2 ;
        RECT 154.650 0.000 154.930 4.000 ;
    END
  END mem_wdata[5]
  PIN mem_wdata[6]
    DIRECTION OUTPUT ;
    USE SIGNAL ;
    ANTENNADIFFAREA 0.340600 ;
    PORT
      LAYER met3 ;
        RECT 0.000 333.240 4.000 333.840 ;
    END
  END mem_wdata[6]
  PIN mem_wdata[7]
    DIRECTION OUTPUT ;
    USE SIGNAL ;
    ANTENNADIFFAREA 0.340600 ;
    PORT
      LAYER met3 ;
        RECT 0.000 129.240 4.000 129.840 ;
    END
  END mem_wdata[7]
  PIN mem_wdata[8]
    DIRECTION OUTPUT ;
    USE SIGNAL ;
    ANTENNADIFFAREA 0.340600 ;
    PORT
      LAYER met3 ;
        RECT 0.000 149.640 4.000 150.240 ;
    END
  END mem_wdata[8]
  PIN mem_wdata[9]
    DIRECTION OUTPUT ;
    USE SIGNAL ;
    ANTENNADIFFAREA 0.340600 ;
    PORT
      LAYER met3 ;
        RECT 0.000 193.840 4.000 194.440 ;
    END
  END mem_wdata[9]
  PIN mem_wstrb[0]
    DIRECTION OUTPUT ;
    USE SIGNAL ;
    ANTENNADIFFAREA 0.340600 ;
    PORT
      LAYER met3 ;
        RECT 428.055 166.640 432.055 167.240 ;
    END
  END mem_wstrb[0]
  PIN mem_wstrb[1]
    DIRECTION OUTPUT ;
    USE SIGNAL ;
    ANTENNADIFFAREA 0.340600 ;
    PORT
      LAYER met3 ;
        RECT 428.055 200.640 432.055 201.240 ;
    END
  END mem_wstrb[1]
  PIN mem_wstrb[2]
    DIRECTION OUTPUT ;
    USE SIGNAL ;
    ANTENNADIFFAREA 0.340600 ;
    PORT
      LAYER met3 ;
        RECT 428.055 204.040 432.055 204.640 ;
    END
  END mem_wstrb[2]
  PIN mem_wstrb[3]
    DIRECTION OUTPUT ;
    USE SIGNAL ;
    ANTENNADIFFAREA 0.340600 ;
    PORT
      LAYER met3 ;
        RECT 428.055 95.240 432.055 95.840 ;
    END
  END mem_wstrb[3]
  PIN pcpi_insn[0]
    DIRECTION OUTPUT ;
    USE SIGNAL ;
    PORT
      LAYER met3 ;
        RECT 428.055 418.240 432.055 418.840 ;
    END
  END pcpi_insn[0]
  PIN pcpi_insn[10]
    DIRECTION OUTPUT ;
    USE SIGNAL ;
    PORT
      LAYER met2 ;
        RECT 341.410 438.775 341.690 442.775 ;
    END
  END pcpi_insn[10]
  PIN pcpi_insn[11]
    DIRECTION OUTPUT ;
    USE SIGNAL ;
    PORT
      LAYER met3 ;
        RECT 428.055 387.640 432.055 388.240 ;
    END
  END pcpi_insn[11]
  PIN pcpi_insn[12]
    DIRECTION OUTPUT ;
    USE SIGNAL ;
    PORT
      LAYER met3 ;
        RECT 428.055 425.040 432.055 425.640 ;
    END
  END pcpi_insn[12]
  PIN pcpi_insn[13]
    DIRECTION OUTPUT ;
    USE SIGNAL ;
    PORT
      LAYER met3 ;
        RECT 428.055 326.440 432.055 327.040 ;
    END
  END pcpi_insn[13]
  PIN pcpi_insn[14]
    DIRECTION OUTPUT ;
    USE SIGNAL ;
    PORT
      LAYER met3 ;
        RECT 428.055 401.240 432.055 401.840 ;
    END
  END pcpi_insn[14]
  PIN pcpi_insn[15]
    DIRECTION OUTPUT ;
    USE SIGNAL ;
    PORT
      LAYER met3 ;
        RECT 428.055 394.440 432.055 395.040 ;
    END
  END pcpi_insn[15]
  PIN pcpi_insn[16]
    DIRECTION OUTPUT ;
    USE SIGNAL ;
    PORT
      LAYER met2 ;
        RECT 351.070 0.000 351.350 4.000 ;
    END
  END pcpi_insn[16]
  PIN pcpi_insn[17]
    DIRECTION OUTPUT ;
    USE SIGNAL ;
    PORT
      LAYER met3 ;
        RECT 428.055 54.440 432.055 55.040 ;
    END
  END pcpi_insn[17]
  PIN pcpi_insn[18]
    DIRECTION OUTPUT ;
    USE SIGNAL ;
    PORT
      LAYER met2 ;
        RECT 399.370 0.000 399.650 4.000 ;
    END
  END pcpi_insn[18]
  PIN pcpi_insn[19]
    DIRECTION OUTPUT ;
    USE SIGNAL ;
    PORT
      LAYER met3 ;
        RECT 428.055 343.440 432.055 344.040 ;
    END
  END pcpi_insn[19]
  PIN pcpi_insn[1]
    DIRECTION OUTPUT ;
    USE SIGNAL ;
    PORT
      LAYER met3 ;
        RECT 428.055 312.840 432.055 313.440 ;
    END
  END pcpi_insn[1]
  PIN pcpi_insn[20]
    DIRECTION OUTPUT ;
    USE SIGNAL ;
    PORT
      LAYER met2 ;
        RECT 396.150 0.000 396.430 4.000 ;
    END
  END pcpi_insn[20]
  PIN pcpi_insn[21]
    DIRECTION OUTPUT ;
    USE SIGNAL ;
    PORT
      LAYER met2 ;
        RECT 370.390 0.000 370.670 4.000 ;
    END
  END pcpi_insn[21]
  PIN pcpi_insn[22]
    DIRECTION OUTPUT ;
    USE SIGNAL ;
    PORT
      LAYER met2 ;
        RECT 363.950 0.000 364.230 4.000 ;
    END
  END pcpi_insn[22]
  PIN pcpi_insn[23]
    DIRECTION OUTPUT ;
    USE SIGNAL ;
    PORT
      LAYER met3 ;
        RECT 428.055 384.240 432.055 384.840 ;
    END
  END pcpi_insn[23]
  PIN pcpi_insn[24]
    DIRECTION OUTPUT ;
    USE SIGNAL ;
    PORT
      LAYER met3 ;
        RECT 428.055 367.240 432.055 367.840 ;
    END
  END pcpi_insn[24]
  PIN pcpi_insn[25]
    DIRECTION OUTPUT ;
    USE SIGNAL ;
    PORT
      LAYER met2 ;
        RECT 412.250 0.000 412.530 4.000 ;
    END
  END pcpi_insn[25]
  PIN pcpi_insn[26]
    DIRECTION OUTPUT ;
    USE SIGNAL ;
    PORT
      LAYER met2 ;
        RECT 412.250 438.775 412.530 442.775 ;
    END
  END pcpi_insn[26]
  PIN pcpi_insn[27]
    DIRECTION OUTPUT ;
    USE SIGNAL ;
    PORT
      LAYER met2 ;
        RECT 347.850 0.000 348.130 4.000 ;
    END
  END pcpi_insn[27]
  PIN pcpi_insn[28]
    DIRECTION OUTPUT ;
    USE SIGNAL ;
    PORT
      LAYER met2 ;
        RECT 376.830 438.775 377.110 442.775 ;
    END
  END pcpi_insn[28]
  PIN pcpi_insn[29]
    DIRECTION OUTPUT ;
    USE SIGNAL ;
    PORT
      LAYER met2 ;
        RECT 409.030 438.775 409.310 442.775 ;
    END
  END pcpi_insn[29]
  PIN pcpi_insn[2]
    DIRECTION OUTPUT ;
    USE SIGNAL ;
    PORT
      LAYER met3 ;
        RECT 428.055 380.840 432.055 381.440 ;
    END
  END pcpi_insn[2]
  PIN pcpi_insn[30]
    DIRECTION OUTPUT ;
    USE SIGNAL ;
    PORT
      LAYER met2 ;
        RECT 334.970 0.000 335.250 4.000 ;
    END
  END pcpi_insn[30]
  PIN pcpi_insn[31]
    DIRECTION OUTPUT ;
    USE SIGNAL ;
    PORT
      LAYER met2 ;
        RECT 389.710 438.775 389.990 442.775 ;
    END
  END pcpi_insn[31]
  PIN pcpi_insn[3]
    DIRECTION OUTPUT ;
    USE SIGNAL ;
    PORT
      LAYER met2 ;
        RECT 367.170 438.775 367.450 442.775 ;
    END
  END pcpi_insn[3]
  PIN pcpi_insn[4]
    DIRECTION OUTPUT ;
    USE SIGNAL ;
    PORT
      LAYER met3 ;
        RECT 428.055 411.440 432.055 412.040 ;
    END
  END pcpi_insn[4]
  PIN pcpi_insn[5]
    DIRECTION OUTPUT ;
    USE SIGNAL ;
    PORT
      LAYER met2 ;
        RECT 386.490 0.000 386.770 4.000 ;
    END
  END pcpi_insn[5]
  PIN pcpi_insn[6]
    DIRECTION OUTPUT ;
    USE SIGNAL ;
    PORT
      LAYER met2 ;
        RECT 312.430 0.000 312.710 4.000 ;
    END
  END pcpi_insn[6]
  PIN pcpi_insn[7]
    DIRECTION OUTPUT ;
    USE SIGNAL ;
    PORT
      LAYER met2 ;
        RECT 389.710 0.000 389.990 4.000 ;
    END
  END pcpi_insn[7]
  PIN pcpi_insn[8]
    DIRECTION OUTPUT ;
    USE SIGNAL ;
    PORT
      LAYER met3 ;
        RECT 428.055 306.040 432.055 306.640 ;
    END
  END pcpi_insn[8]
  PIN pcpi_insn[9]
    DIRECTION OUTPUT ;
    USE SIGNAL ;
    PORT
      LAYER met3 ;
        RECT 428.055 428.440 432.055 429.040 ;
    END
  END pcpi_insn[9]
  PIN pcpi_rd[0]
    DIRECTION INPUT ;
    USE SIGNAL ;
    PORT
      LAYER met2 ;
        RECT 338.190 0.000 338.470 4.000 ;
    END
  END pcpi_rd[0]
  PIN pcpi_rd[10]
    DIRECTION INPUT ;
    USE SIGNAL ;
    PORT
      LAYER met2 ;
        RECT 6.530 0.000 6.810 4.000 ;
    END
  END pcpi_rd[10]
  PIN pcpi_rd[11]
    DIRECTION INPUT ;
    USE SIGNAL ;
    PORT
      LAYER met2 ;
        RECT 128.890 0.000 129.170 4.000 ;
    END
  END pcpi_rd[11]
  PIN pcpi_rd[12]
    DIRECTION INPUT ;
    USE SIGNAL ;
    PORT
      LAYER met2 ;
        RECT 428.350 0.000 428.630 4.000 ;
    END
  END pcpi_rd[12]
  PIN pcpi_rd[13]
    DIRECTION INPUT ;
    USE SIGNAL ;
    PORT
      LAYER met2 ;
        RECT 48.390 0.000 48.670 4.000 ;
    END
  END pcpi_rd[13]
  PIN pcpi_rd[14]
    DIRECTION INPUT ;
    USE SIGNAL ;
    PORT
      LAYER met2 ;
        RECT 148.210 0.000 148.490 4.000 ;
    END
  END pcpi_rd[14]
  PIN pcpi_rd[15]
    DIRECTION INPUT ;
    USE SIGNAL ;
    PORT
      LAYER met2 ;
        RECT 260.910 0.000 261.190 4.000 ;
    END
  END pcpi_rd[15]
  PIN pcpi_rd[16]
    DIRECTION INPUT ;
    USE SIGNAL ;
    PORT
      LAYER met2 ;
        RECT 83.810 0.000 84.090 4.000 ;
    END
  END pcpi_rd[16]
  PIN pcpi_rd[17]
    DIRECTION INPUT ;
    USE SIGNAL ;
    PORT
      LAYER met2 ;
        RECT 132.110 0.000 132.390 4.000 ;
    END
  END pcpi_rd[17]
  PIN pcpi_rd[18]
    DIRECTION INPUT ;
    USE SIGNAL ;
    PORT
      LAYER met2 ;
        RECT 151.430 0.000 151.710 4.000 ;
    END
  END pcpi_rd[18]
  PIN pcpi_rd[19]
    DIRECTION INPUT ;
    USE SIGNAL ;
    PORT
      LAYER met2 ;
        RECT 193.290 0.000 193.570 4.000 ;
    END
  END pcpi_rd[19]
  PIN pcpi_rd[1]
    DIRECTION INPUT ;
    USE SIGNAL ;
    PORT
      LAYER met2 ;
        RECT 141.770 0.000 142.050 4.000 ;
    END
  END pcpi_rd[1]
  PIN pcpi_rd[20]
    DIRECTION INPUT ;
    USE SIGNAL ;
    PORT
      LAYER met2 ;
        RECT 29.070 0.000 29.350 4.000 ;
    END
  END pcpi_rd[20]
  PIN pcpi_rd[21]
    DIRECTION INPUT ;
    USE SIGNAL ;
    PORT
      LAYER met2 ;
        RECT 318.870 0.000 319.150 4.000 ;
    END
  END pcpi_rd[21]
  PIN pcpi_rd[22]
    DIRECTION INPUT ;
    USE SIGNAL ;
    PORT
      LAYER met2 ;
        RECT 325.310 0.000 325.590 4.000 ;
    END
  END pcpi_rd[22]
  PIN pcpi_rd[23]
    DIRECTION INPUT ;
    USE SIGNAL ;
    PORT
      LAYER met2 ;
        RECT 277.010 0.000 277.290 4.000 ;
    END
  END pcpi_rd[23]
  PIN pcpi_rd[24]
    DIRECTION INPUT ;
    USE SIGNAL ;
    PORT
      LAYER met2 ;
        RECT 16.190 0.000 16.470 4.000 ;
    END
  END pcpi_rd[24]
  PIN pcpi_rd[25]
    DIRECTION INPUT ;
    USE SIGNAL ;
    PORT
      LAYER met2 ;
        RECT 12.970 0.000 13.250 4.000 ;
    END
  END pcpi_rd[25]
  PIN pcpi_rd[26]
    DIRECTION INPUT ;
    USE SIGNAL ;
    PORT
      LAYER met2 ;
        RECT 322.090 0.000 322.370 4.000 ;
    END
  END pcpi_rd[26]
  PIN pcpi_rd[27]
    DIRECTION INPUT ;
    USE SIGNAL ;
    PORT
      LAYER met2 ;
        RECT 25.850 0.000 26.130 4.000 ;
    END
  END pcpi_rd[27]
  PIN pcpi_rd[28]
    DIRECTION INPUT ;
    USE SIGNAL ;
    PORT
      LAYER met2 ;
        RECT 3.310 0.000 3.590 4.000 ;
    END
  END pcpi_rd[28]
  PIN pcpi_rd[29]
    DIRECTION INPUT ;
    USE SIGNAL ;
    PORT
      LAYER met2 ;
        RECT 38.730 0.000 39.010 4.000 ;
    END
  END pcpi_rd[29]
  PIN pcpi_rd[2]
    DIRECTION INPUT ;
    USE SIGNAL ;
    PORT
      LAYER met2 ;
        RECT 273.790 0.000 274.070 4.000 ;
    END
  END pcpi_rd[2]
  PIN pcpi_rd[30]
    DIRECTION INPUT ;
    USE SIGNAL ;
    PORT
      LAYER met2 ;
        RECT 9.750 0.000 10.030 4.000 ;
    END
  END pcpi_rd[30]
  PIN pcpi_rd[31]
    DIRECTION INPUT ;
    USE SIGNAL ;
    PORT
      LAYER met2 ;
        RECT 254.470 0.000 254.750 4.000 ;
    END
  END pcpi_rd[31]
  PIN pcpi_rd[3]
    DIRECTION INPUT ;
    USE SIGNAL ;
    PORT
      LAYER met2 ;
        RECT 280.230 0.000 280.510 4.000 ;
    END
  END pcpi_rd[3]
  PIN pcpi_rd[4]
    DIRECTION INPUT ;
    USE SIGNAL ;
    PORT
      LAYER met2 ;
        RECT 35.510 0.000 35.790 4.000 ;
    END
  END pcpi_rd[4]
  PIN pcpi_rd[5]
    DIRECTION INPUT ;
    USE SIGNAL ;
    PORT
      LAYER met2 ;
        RECT 418.690 0.000 418.970 4.000 ;
    END
  END pcpi_rd[5]
  PIN pcpi_rd[6]
    DIRECTION INPUT ;
    USE SIGNAL ;
    PORT
      LAYER met2 ;
        RECT 109.570 0.000 109.850 4.000 ;
    END
  END pcpi_rd[6]
  PIN pcpi_rd[7]
    DIRECTION INPUT ;
    USE SIGNAL ;
    PORT
      LAYER met2 ;
        RECT 19.410 0.000 19.690 4.000 ;
    END
  END pcpi_rd[7]
  PIN pcpi_rd[8]
    DIRECTION INPUT ;
    USE SIGNAL ;
    PORT
      LAYER met2 ;
        RECT 405.810 0.000 406.090 4.000 ;
    END
  END pcpi_rd[8]
  PIN pcpi_rd[9]
    DIRECTION INPUT ;
    USE SIGNAL ;
    PORT
      LAYER met2 ;
        RECT 425.130 0.000 425.410 4.000 ;
    END
  END pcpi_rd[9]
  PIN pcpi_ready
    DIRECTION INPUT ;
    USE SIGNAL ;
    PORT
      LAYER met2 ;
        RECT 32.290 0.000 32.570 4.000 ;
    END
  END pcpi_ready
  PIN pcpi_rs1[0]
    DIRECTION OUTPUT ;
    USE SIGNAL ;
    ANTENNADIFFAREA 0.340600 ;
    PORT
      LAYER met3 ;
        RECT 428.055 88.440 432.055 89.040 ;
    END
  END pcpi_rs1[0]
  PIN pcpi_rs1[10]
    DIRECTION OUTPUT ;
    USE SIGNAL ;
    ANTENNADIFFAREA 0.340600 ;
    PORT
      LAYER met2 ;
        RECT 190.070 0.000 190.350 4.000 ;
    END
  END pcpi_rs1[10]
  PIN pcpi_rs1[11]
    DIRECTION OUTPUT ;
    USE SIGNAL ;
    ANTENNADIFFAREA 0.340600 ;
    PORT
      LAYER met3 ;
        RECT 428.055 30.640 432.055 31.240 ;
    END
  END pcpi_rs1[11]
  PIN pcpi_rs1[12]
    DIRECTION OUTPUT ;
    USE SIGNAL ;
    ANTENNADIFFAREA 0.340600 ;
    PORT
      LAYER met3 ;
        RECT 0.000 210.840 4.000 211.440 ;
    END
  END pcpi_rs1[12]
  PIN pcpi_rs1[13]
    DIRECTION OUTPUT ;
    USE SIGNAL ;
    ANTENNADIFFAREA 0.340600 ;
    PORT
      LAYER met3 ;
        RECT 0.000 238.040 4.000 238.640 ;
    END
  END pcpi_rs1[13]
  PIN pcpi_rs1[14]
    DIRECTION OUTPUT ;
    USE SIGNAL ;
    ANTENNADIFFAREA 0.340600 ;
    PORT
      LAYER met2 ;
        RECT 206.170 438.775 206.450 442.775 ;
    END
  END pcpi_rs1[14]
  PIN pcpi_rs1[15]
    DIRECTION OUTPUT ;
    USE SIGNAL ;
    ANTENNADIFFAREA 0.340600 ;
    PORT
      LAYER met3 ;
        RECT 428.055 265.240 432.055 265.840 ;
    END
  END pcpi_rs1[15]
  PIN pcpi_rs1[16]
    DIRECTION OUTPUT ;
    USE SIGNAL ;
    ANTENNADIFFAREA 0.340600 ;
    PORT
      LAYER met3 ;
        RECT 428.055 278.840 432.055 279.440 ;
    END
  END pcpi_rs1[16]
  PIN pcpi_rs1[17]
    DIRECTION OUTPUT ;
    USE SIGNAL ;
    ANTENNADIFFAREA 0.340600 ;
    PORT
      LAYER met3 ;
        RECT 428.055 289.040 432.055 289.640 ;
    END
  END pcpi_rs1[17]
  PIN pcpi_rs1[18]
    DIRECTION OUTPUT ;
    USE SIGNAL ;
    ANTENNADIFFAREA 0.340600 ;
    PORT
      LAYER met3 ;
        RECT 428.055 275.440 432.055 276.040 ;
    END
  END pcpi_rs1[18]
  PIN pcpi_rs1[19]
    DIRECTION OUTPUT ;
    USE SIGNAL ;
    ANTENNADIFFAREA 0.340600 ;
    PORT
      LAYER met2 ;
        RECT 309.210 438.775 309.490 442.775 ;
    END
  END pcpi_rs1[19]
  PIN pcpi_rs1[1]
    DIRECTION OUTPUT ;
    USE SIGNAL ;
    ANTENNADIFFAREA 0.340600 ;
    PORT
      LAYER met3 ;
        RECT 428.055 78.240 432.055 78.840 ;
    END
  END pcpi_rs1[1]
  PIN pcpi_rs1[20]
    DIRECTION OUTPUT ;
    USE SIGNAL ;
    ANTENNADIFFAREA 0.340600 ;
    PORT
      LAYER met2 ;
        RECT 351.070 438.775 351.350 442.775 ;
    END
  END pcpi_rs1[20]
  PIN pcpi_rs1[21]
    DIRECTION OUTPUT ;
    USE SIGNAL ;
    ANTENNADIFFAREA 0.340600 ;
    PORT
      LAYER met2 ;
        RECT 347.850 438.775 348.130 442.775 ;
    END
  END pcpi_rs1[21]
  PIN pcpi_rs1[22]
    DIRECTION OUTPUT ;
    USE SIGNAL ;
    ANTENNADIFFAREA 0.340600 ;
    PORT
      LAYER met2 ;
        RECT 280.230 438.775 280.510 442.775 ;
    END
  END pcpi_rs1[22]
  PIN pcpi_rs1[23]
    DIRECTION OUTPUT ;
    USE SIGNAL ;
    ANTENNADIFFAREA 0.340600 ;
    PORT
      LAYER met2 ;
        RECT 293.110 438.775 293.390 442.775 ;
    END
  END pcpi_rs1[23]
  PIN pcpi_rs1[24]
    DIRECTION OUTPUT ;
    USE SIGNAL ;
    ANTENNADIFFAREA 0.340600 ;
    PORT
      LAYER met2 ;
        RECT 344.630 438.775 344.910 442.775 ;
    END
  END pcpi_rs1[24]
  PIN pcpi_rs1[25]
    DIRECTION OUTPUT ;
    USE SIGNAL ;
    ANTENNADIFFAREA 0.340600 ;
    PORT
      LAYER met2 ;
        RECT 338.190 438.775 338.470 442.775 ;
    END
  END pcpi_rs1[25]
  PIN pcpi_rs1[26]
    DIRECTION OUTPUT ;
    USE SIGNAL ;
    ANTENNADIFFAREA 0.340600 ;
    PORT
      LAYER met2 ;
        RECT 334.970 438.775 335.250 442.775 ;
    END
  END pcpi_rs1[26]
  PIN pcpi_rs1[27]
    DIRECTION OUTPUT ;
    USE SIGNAL ;
    ANTENNADIFFAREA 0.340600 ;
    PORT
      LAYER met2 ;
        RECT 248.030 438.775 248.310 442.775 ;
    END
  END pcpi_rs1[27]
  PIN pcpi_rs1[28]
    DIRECTION OUTPUT ;
    USE SIGNAL ;
    ANTENNADIFFAREA 0.340600 ;
    PORT
      LAYER met2 ;
        RECT 251.250 438.775 251.530 442.775 ;
    END
  END pcpi_rs1[28]
  PIN pcpi_rs1[29]
    DIRECTION OUTPUT ;
    USE SIGNAL ;
    ANTENNADIFFAREA 0.340600 ;
    PORT
      LAYER met2 ;
        RECT 219.050 438.775 219.330 442.775 ;
    END
  END pcpi_rs1[29]
  PIN pcpi_rs1[2]
    DIRECTION OUTPUT ;
    USE SIGNAL ;
    ANTENNADIFFAREA 0.340600 ;
    PORT
      LAYER met2 ;
        RECT 264.130 0.000 264.410 4.000 ;
    END
  END pcpi_rs1[2]
  PIN pcpi_rs1[30]
    DIRECTION OUTPUT ;
    USE SIGNAL ;
    ANTENNADIFFAREA 0.340600 ;
    PORT
      LAYER met2 ;
        RECT 212.610 438.775 212.890 442.775 ;
    END
  END pcpi_rs1[30]
  PIN pcpi_rs1[31]
    DIRECTION OUTPUT ;
    USE SIGNAL ;
    ANTENNADIFFAREA 0.340600 ;
    PORT
      LAYER met3 ;
        RECT 428.055 248.240 432.055 248.840 ;
    END
  END pcpi_rs1[31]
  PIN pcpi_rs1[3]
    DIRECTION OUTPUT ;
    USE SIGNAL ;
    ANTENNADIFFAREA 0.340600 ;
    PORT
      LAYER met2 ;
        RECT 202.950 0.000 203.230 4.000 ;
    END
  END pcpi_rs1[3]
  PIN pcpi_rs1[4]
    DIRECTION OUTPUT ;
    USE SIGNAL ;
    ANTENNADIFFAREA 0.340600 ;
    PORT
      LAYER met2 ;
        RECT 257.690 0.000 257.970 4.000 ;
    END
  END pcpi_rs1[4]
  PIN pcpi_rs1[5]
    DIRECTION OUTPUT ;
    USE SIGNAL ;
    ANTENNADIFFAREA 0.340600 ;
    PORT
      LAYER met3 ;
        RECT 428.055 74.840 432.055 75.440 ;
    END
  END pcpi_rs1[5]
  PIN pcpi_rs1[6]
    DIRECTION OUTPUT ;
    USE SIGNAL ;
    ANTENNADIFFAREA 0.340600 ;
    PORT
      LAYER met2 ;
        RECT 183.630 0.000 183.910 4.000 ;
    END
  END pcpi_rs1[6]
  PIN pcpi_rs1[7]
    DIRECTION OUTPUT ;
    USE SIGNAL ;
    ANTENNADIFFAREA 0.340600 ;
    PORT
      LAYER met2 ;
        RECT 286.670 0.000 286.950 4.000 ;
    END
  END pcpi_rs1[7]
  PIN pcpi_rs1[8]
    DIRECTION OUTPUT ;
    USE SIGNAL ;
    ANTENNADIFFAREA 0.340600 ;
    PORT
      LAYER met3 ;
        RECT 428.055 71.440 432.055 72.040 ;
    END
  END pcpi_rs1[8]
  PIN pcpi_rs1[9]
    DIRECTION OUTPUT ;
    USE SIGNAL ;
    ANTENNADIFFAREA 0.340600 ;
    PORT
      LAYER met3 ;
        RECT 428.055 68.040 432.055 68.640 ;
    END
  END pcpi_rs1[9]
  PIN pcpi_rs2[0]
    DIRECTION OUTPUT ;
    USE SIGNAL ;
    ANTENNADIFFAREA 0.340600 ;
    PORT
      LAYER met2 ;
        RECT 177.190 0.000 177.470 4.000 ;
    END
  END pcpi_rs2[0]
  PIN pcpi_rs2[10]
    DIRECTION OUTPUT ;
    USE SIGNAL ;
    ANTENNADIFFAREA 0.340600 ;
    PORT
      LAYER met3 ;
        RECT 0.000 176.840 4.000 177.440 ;
    END
  END pcpi_rs2[10]
  PIN pcpi_rs2[11]
    DIRECTION OUTPUT ;
    USE SIGNAL ;
    ANTENNADIFFAREA 0.340600 ;
    PORT
      LAYER met3 ;
        RECT 0.000 125.840 4.000 126.440 ;
    END
  END pcpi_rs2[11]
  PIN pcpi_rs2[12]
    DIRECTION OUTPUT ;
    USE SIGNAL ;
    ANTENNADIFFAREA 0.340600 ;
    PORT
      LAYER met3 ;
        RECT 0.000 207.440 4.000 208.040 ;
    END
  END pcpi_rs2[12]
  PIN pcpi_rs2[13]
    DIRECTION OUTPUT ;
    USE SIGNAL ;
    ANTENNADIFFAREA 0.340600 ;
    PORT
      LAYER met3 ;
        RECT 0.000 234.640 4.000 235.240 ;
    END
  END pcpi_rs2[13]
  PIN pcpi_rs2[14]
    DIRECTION OUTPUT ;
    USE SIGNAL ;
    ANTENNADIFFAREA 0.340600 ;
    PORT
      LAYER met3 ;
        RECT 0.000 227.840 4.000 228.440 ;
    END
  END pcpi_rs2[14]
  PIN pcpi_rs2[15]
    DIRECTION OUTPUT ;
    USE SIGNAL ;
    ANTENNADIFFAREA 0.340600 ;
    PORT
      LAYER met3 ;
        RECT 0.000 231.240 4.000 231.840 ;
    END
  END pcpi_rs2[15]
  PIN pcpi_rs2[16]
    DIRECTION OUTPUT ;
    USE SIGNAL ;
    ANTENNADIFFAREA 0.340600 ;
    PORT
      LAYER met2 ;
        RECT 289.890 438.775 290.170 442.775 ;
    END
  END pcpi_rs2[16]
  PIN pcpi_rs2[17]
    DIRECTION OUTPUT ;
    USE SIGNAL ;
    ANTENNADIFFAREA 0.340600 ;
    PORT
      LAYER met2 ;
        RECT 190.070 438.775 190.350 442.775 ;
    END
  END pcpi_rs2[17]
  PIN pcpi_rs2[18]
    DIRECTION OUTPUT ;
    USE SIGNAL ;
    ANTENNADIFFAREA 0.340600 ;
    PORT
      LAYER met2 ;
        RECT 173.970 438.775 174.250 442.775 ;
    END
  END pcpi_rs2[18]
  PIN pcpi_rs2[19]
    DIRECTION OUTPUT ;
    USE SIGNAL ;
    ANTENNADIFFAREA 0.340600 ;
    PORT
      LAYER met2 ;
        RECT 183.630 438.775 183.910 442.775 ;
    END
  END pcpi_rs2[19]
  PIN pcpi_rs2[1]
    DIRECTION OUTPUT ;
    USE SIGNAL ;
    ANTENNADIFFAREA 0.340600 ;
    PORT
      LAYER met2 ;
        RECT 173.970 0.000 174.250 4.000 ;
    END
  END pcpi_rs2[1]
  PIN pcpi_rs2[20]
    DIRECTION OUTPUT ;
    USE SIGNAL ;
    ANTENNADIFFAREA 0.340600 ;
    PORT
      LAYER met2 ;
        RECT 302.770 438.775 303.050 442.775 ;
    END
  END pcpi_rs2[20]
  PIN pcpi_rs2[21]
    DIRECTION OUTPUT ;
    USE SIGNAL ;
    ANTENNADIFFAREA 0.340600 ;
    PORT
      LAYER met2 ;
        RECT 215.830 438.775 216.110 442.775 ;
    END
  END pcpi_rs2[21]
  PIN pcpi_rs2[22]
    DIRECTION OUTPUT ;
    USE SIGNAL ;
    ANTENNADIFFAREA 0.340600 ;
    PORT
      LAYER met2 ;
        RECT 180.410 438.775 180.690 442.775 ;
    END
  END pcpi_rs2[22]
  PIN pcpi_rs2[23]
    DIRECTION OUTPUT ;
    USE SIGNAL ;
    ANTENNADIFFAREA 0.340600 ;
    PORT
      LAYER met2 ;
        RECT 177.190 438.775 177.470 442.775 ;
    END
  END pcpi_rs2[23]
  PIN pcpi_rs2[24]
    DIRECTION OUTPUT ;
    USE SIGNAL ;
    ANTENNADIFFAREA 0.340600 ;
    PORT
      LAYER met2 ;
        RECT 170.750 438.775 171.030 442.775 ;
    END
  END pcpi_rs2[24]
  PIN pcpi_rs2[25]
    DIRECTION OUTPUT ;
    USE SIGNAL ;
    ANTENNADIFFAREA 0.340600 ;
    PORT
      LAYER met2 ;
        RECT 154.650 438.775 154.930 442.775 ;
    END
  END pcpi_rs2[25]
  PIN pcpi_rs2[26]
    DIRECTION OUTPUT ;
    USE SIGNAL ;
    ANTENNADIFFAREA 0.340600 ;
    PORT
      LAYER met2 ;
        RECT 151.430 438.775 151.710 442.775 ;
    END
  END pcpi_rs2[26]
  PIN pcpi_rs2[27]
    DIRECTION OUTPUT ;
    USE SIGNAL ;
    ANTENNADIFFAREA 0.340600 ;
    PORT
      LAYER met2 ;
        RECT 209.390 438.775 209.670 442.775 ;
    END
  END pcpi_rs2[27]
  PIN pcpi_rs2[28]
    DIRECTION OUTPUT ;
    USE SIGNAL ;
    ANTENNADIFFAREA 0.340600 ;
    PORT
      LAYER met2 ;
        RECT 196.510 438.775 196.790 442.775 ;
    END
  END pcpi_rs2[28]
  PIN pcpi_rs2[29]
    DIRECTION OUTPUT ;
    USE SIGNAL ;
    ANTENNADIFFAREA 0.340600 ;
    PORT
      LAYER met3 ;
        RECT 0.000 292.440 4.000 293.040 ;
    END
  END pcpi_rs2[29]
  PIN pcpi_rs2[2]
    DIRECTION OUTPUT ;
    USE SIGNAL ;
    ANTENNADIFFAREA 0.340600 ;
    PORT
      LAYER met2 ;
        RECT 164.310 0.000 164.590 4.000 ;
    END
  END pcpi_rs2[2]
  PIN pcpi_rs2[30]
    DIRECTION OUTPUT ;
    USE SIGNAL ;
    ANTENNADIFFAREA 0.340600 ;
    PORT
      LAYER met3 ;
        RECT 0.000 265.240 4.000 265.840 ;
    END
  END pcpi_rs2[30]
  PIN pcpi_rs2[31]
    DIRECTION OUTPUT ;
    USE SIGNAL ;
    ANTENNADIFFAREA 0.340600 ;
    PORT
      LAYER met2 ;
        RECT 193.290 438.775 193.570 442.775 ;
    END
  END pcpi_rs2[31]
  PIN pcpi_rs2[3]
    DIRECTION OUTPUT ;
    USE SIGNAL ;
    ANTENNADIFFAREA 0.340600 ;
    PORT
      LAYER met2 ;
        RECT 167.530 0.000 167.810 4.000 ;
    END
  END pcpi_rs2[3]
  PIN pcpi_rs2[4]
    DIRECTION OUTPUT ;
    USE SIGNAL ;
    ANTENNADIFFAREA 0.340600 ;
    PORT
      LAYER met2 ;
        RECT 170.750 0.000 171.030 4.000 ;
    END
  END pcpi_rs2[4]
  PIN pcpi_rs2[5]
    DIRECTION OUTPUT ;
    USE SIGNAL ;
    ANTENNADIFFAREA 0.340600 ;
    PORT
      LAYER met2 ;
        RECT 161.090 0.000 161.370 4.000 ;
    END
  END pcpi_rs2[5]
  PIN pcpi_rs2[6]
    DIRECTION OUTPUT ;
    USE SIGNAL ;
    ANTENNADIFFAREA 0.340600 ;
    PORT
      LAYER met3 ;
        RECT 0.000 170.040 4.000 170.640 ;
    END
  END pcpi_rs2[6]
  PIN pcpi_rs2[7]
    DIRECTION OUTPUT ;
    USE SIGNAL ;
    ANTENNADIFFAREA 0.340600 ;
    PORT
      LAYER met3 ;
        RECT 0.000 139.440 4.000 140.040 ;
    END
  END pcpi_rs2[7]
  PIN pcpi_rs2[8]
    DIRECTION OUTPUT ;
    USE SIGNAL ;
    ANTENNADIFFAREA 0.340600 ;
    PORT
      LAYER met3 ;
        RECT 0.000 180.240 4.000 180.840 ;
    END
  END pcpi_rs2[8]
  PIN pcpi_rs2[9]
    DIRECTION OUTPUT ;
    USE SIGNAL ;
    ANTENNADIFFAREA 0.340600 ;
    PORT
      LAYER met3 ;
        RECT 0.000 187.040 4.000 187.640 ;
    END
  END pcpi_rs2[9]
  PIN pcpi_valid
    DIRECTION OUTPUT ;
    USE SIGNAL ;
    PORT
      LAYER met2 ;
        RECT 354.290 0.000 354.570 4.000 ;
    END
  END pcpi_valid
  PIN pcpi_wait
    DIRECTION INPUT ;
    USE SIGNAL ;
    PORT
      LAYER met2 ;
        RECT 125.670 0.000 125.950 4.000 ;
    END
  END pcpi_wait
  PIN pcpi_wr
    DIRECTION INPUT ;
    USE SIGNAL ;
    PORT
      LAYER met2 ;
        RECT 58.050 0.000 58.330 4.000 ;
    END
  END pcpi_wr
  PIN resetn
    DIRECTION INPUT ;
    USE SIGNAL ;
    ANTENNAGATEAREA 0.852000 ;
    PORT
      LAYER met3 ;
        RECT 428.055 6.840 432.055 7.440 ;
    END
  END resetn
  PIN trace_data[0]
    DIRECTION OUTPUT ;
    USE SIGNAL ;
    PORT
      LAYER met3 ;
        RECT 428.055 346.840 432.055 347.440 ;
    END
  END trace_data[0]
  PIN trace_data[10]
    DIRECTION OUTPUT ;
    USE SIGNAL ;
    PORT
      LAYER met2 ;
        RECT 386.490 438.775 386.770 442.775 ;
    END
  END trace_data[10]
  PIN trace_data[11]
    DIRECTION OUTPUT ;
    USE SIGNAL ;
    PORT
      LAYER met2 ;
        RECT 299.550 0.000 299.830 4.000 ;
    END
  END trace_data[11]
  PIN trace_data[12]
    DIRECTION OUTPUT ;
    USE SIGNAL ;
    PORT
      LAYER met3 ;
        RECT 428.055 10.240 432.055 10.840 ;
    END
  END trace_data[12]
  PIN trace_data[13]
    DIRECTION OUTPUT ;
    USE SIGNAL ;
    PORT
      LAYER met3 ;
        RECT 428.055 340.040 432.055 340.640 ;
    END
  END trace_data[13]
  PIN trace_data[14]
    DIRECTION OUTPUT ;
    USE SIGNAL ;
    PORT
      LAYER met3 ;
        RECT 428.055 37.440 432.055 38.040 ;
    END
  END trace_data[14]
  PIN trace_data[15]
    DIRECTION OUTPUT ;
    USE SIGNAL ;
    PORT
      LAYER met3 ;
        RECT 428.055 360.440 432.055 361.040 ;
    END
  END trace_data[15]
  PIN trace_data[16]
    DIRECTION OUTPUT ;
    USE SIGNAL ;
    PORT
      LAYER met2 ;
        RECT 383.270 0.000 383.550 4.000 ;
    END
  END trace_data[16]
  PIN trace_data[17]
    DIRECTION OUTPUT ;
    USE SIGNAL ;
    PORT
      LAYER met3 ;
        RECT 428.055 431.840 432.055 432.440 ;
    END
  END trace_data[17]
  PIN trace_data[18]
    DIRECTION OUTPUT ;
    USE SIGNAL ;
    PORT
      LAYER met2 ;
        RECT 360.730 0.000 361.010 4.000 ;
    END
  END trace_data[18]
  PIN trace_data[19]
    DIRECTION OUTPUT ;
    USE SIGNAL ;
    PORT
      LAYER met2 ;
        RECT 302.770 0.000 303.050 4.000 ;
    END
  END trace_data[19]
  PIN trace_data[1]
    DIRECTION OUTPUT ;
    USE SIGNAL ;
    PORT
      LAYER met3 ;
        RECT 428.055 57.840 432.055 58.440 ;
    END
  END trace_data[1]
  PIN trace_data[20]
    DIRECTION OUTPUT ;
    USE SIGNAL ;
    PORT
      LAYER met2 ;
        RECT 392.930 0.000 393.210 4.000 ;
    END
  END trace_data[20]
  PIN trace_data[21]
    DIRECTION OUTPUT ;
    USE SIGNAL ;
    PORT
      LAYER met3 ;
        RECT 428.055 397.840 432.055 398.440 ;
    END
  END trace_data[21]
  PIN trace_data[22]
    DIRECTION OUTPUT ;
    USE SIGNAL ;
    PORT
      LAYER met3 ;
        RECT 428.055 435.240 432.055 435.840 ;
    END
  END trace_data[22]
  PIN trace_data[23]
    DIRECTION OUTPUT ;
    USE SIGNAL ;
    PORT
      LAYER met2 ;
        RECT 402.590 0.000 402.870 4.000 ;
    END
  END trace_data[23]
  PIN trace_data[24]
    DIRECTION OUTPUT ;
    USE SIGNAL ;
    PORT
      LAYER met2 ;
        RECT 305.990 0.000 306.270 4.000 ;
    END
  END trace_data[24]
  PIN trace_data[25]
    DIRECTION OUTPUT ;
    USE SIGNAL ;
    PORT
      LAYER met3 ;
        RECT 428.055 438.640 432.055 439.240 ;
    END
  END trace_data[25]
  PIN trace_data[26]
    DIRECTION OUTPUT ;
    USE SIGNAL ;
    PORT
      LAYER met2 ;
        RECT 328.530 0.000 328.810 4.000 ;
    END
  END trace_data[26]
  PIN trace_data[27]
    DIRECTION OUTPUT ;
    USE SIGNAL ;
    PORT
      LAYER met3 ;
        RECT 428.055 34.040 432.055 34.640 ;
    END
  END trace_data[27]
  PIN trace_data[28]
    DIRECTION OUTPUT ;
    USE SIGNAL ;
    PORT
      LAYER met3 ;
        RECT 428.055 319.640 432.055 320.240 ;
    END
  END trace_data[28]
  PIN trace_data[29]
    DIRECTION OUTPUT ;
    USE SIGNAL ;
    PORT
      LAYER met2 ;
        RECT 380.050 438.775 380.330 442.775 ;
    END
  END trace_data[29]
  PIN trace_data[2]
    DIRECTION OUTPUT ;
    USE SIGNAL ;
    PORT
      LAYER met3 ;
        RECT 428.055 350.240 432.055 350.840 ;
    END
  END trace_data[2]
  PIN trace_data[30]
    DIRECTION OUTPUT ;
    USE SIGNAL ;
    PORT
      LAYER met3 ;
        RECT 428.055 414.840 432.055 415.440 ;
    END
  END trace_data[30]
  PIN trace_data[31]
    DIRECTION OUTPUT ;
    USE SIGNAL ;
    PORT
      LAYER met2 ;
        RECT 405.810 438.775 406.090 442.775 ;
    END
  END trace_data[31]
  PIN trace_data[32]
    DIRECTION OUTPUT ;
    USE SIGNAL ;
    PORT
      LAYER met2 ;
        RECT 357.510 0.000 357.790 4.000 ;
    END
  END trace_data[32]
  PIN trace_data[33]
    DIRECTION OUTPUT ;
    USE SIGNAL ;
    PORT
      LAYER met2 ;
        RECT 376.830 0.000 377.110 4.000 ;
    END
  END trace_data[33]
  PIN trace_data[34]
    DIRECTION OUTPUT ;
    USE SIGNAL ;
    PORT
      LAYER met3 ;
        RECT 428.055 316.240 432.055 316.840 ;
    END
  END trace_data[34]
  PIN trace_data[35]
    DIRECTION OUTPUT ;
    USE SIGNAL ;
    PORT
      LAYER met2 ;
        RECT 367.170 0.000 367.450 4.000 ;
    END
  END trace_data[35]
  PIN trace_data[3]
    DIRECTION OUTPUT ;
    USE SIGNAL ;
    PORT
      LAYER met2 ;
        RECT 399.370 438.775 399.650 442.775 ;
    END
  END trace_data[3]
  PIN trace_data[4]
    DIRECTION OUTPUT ;
    USE SIGNAL ;
    PORT
      LAYER met3 ;
        RECT 428.055 17.040 432.055 17.640 ;
    END
  END trace_data[4]
  PIN trace_data[5]
    DIRECTION OUTPUT ;
    USE SIGNAL ;
    PORT
      LAYER met3 ;
        RECT 428.055 40.840 432.055 41.440 ;
    END
  END trace_data[5]
  PIN trace_data[6]
    DIRECTION OUTPUT ;
    USE SIGNAL ;
    PORT
      LAYER met3 ;
        RECT 428.055 27.240 432.055 27.840 ;
    END
  END trace_data[6]
  PIN trace_data[7]
    DIRECTION OUTPUT ;
    USE SIGNAL ;
    PORT
      LAYER met3 ;
        RECT 428.055 442.040 432.055 442.640 ;
    END
  END trace_data[7]
  PIN trace_data[8]
    DIRECTION OUTPUT ;
    USE SIGNAL ;
    PORT
      LAYER met3 ;
        RECT 428.055 20.440 432.055 21.040 ;
    END
  END trace_data[8]
  PIN trace_data[9]
    DIRECTION OUTPUT ;
    USE SIGNAL ;
    PORT
      LAYER met3 ;
        RECT 428.055 370.640 432.055 371.240 ;
    END
  END trace_data[9]
  PIN trace_valid
    DIRECTION OUTPUT ;
    USE SIGNAL ;
    PORT
      LAYER met2 ;
        RECT 421.910 438.775 422.190 442.775 ;
    END
  END trace_valid
  PIN trap
    DIRECTION OUTPUT ;
    USE SIGNAL ;
    ANTENNADIFFAREA 0.340600 ;
    PORT
      LAYER met3 ;
        RECT 0.000 119.040 4.000 119.640 ;
    END
  END trap
  OBS
      LAYER nwell ;
        RECT 5.330 10.795 426.610 429.845 ;
      LAYER li1 ;
        RECT 5.520 10.795 426.420 429.845 ;
      LAYER met1 ;
        RECT 4.210 9.220 428.650 431.080 ;
      LAYER met2 ;
        RECT 4.230 438.495 151.150 442.525 ;
        RECT 151.990 438.495 154.370 442.525 ;
        RECT 155.210 438.495 157.590 442.525 ;
        RECT 158.430 438.495 160.810 442.525 ;
        RECT 161.650 438.495 164.030 442.525 ;
        RECT 164.870 438.495 167.250 442.525 ;
        RECT 168.090 438.495 170.470 442.525 ;
        RECT 171.310 438.495 173.690 442.525 ;
        RECT 174.530 438.495 176.910 442.525 ;
        RECT 177.750 438.495 180.130 442.525 ;
        RECT 180.970 438.495 183.350 442.525 ;
        RECT 184.190 438.495 186.570 442.525 ;
        RECT 187.410 438.495 189.790 442.525 ;
        RECT 190.630 438.495 193.010 442.525 ;
        RECT 193.850 438.495 196.230 442.525 ;
        RECT 197.070 438.495 199.450 442.525 ;
        RECT 200.290 438.495 202.670 442.525 ;
        RECT 203.510 438.495 205.890 442.525 ;
        RECT 206.730 438.495 209.110 442.525 ;
        RECT 209.950 438.495 212.330 442.525 ;
        RECT 213.170 438.495 215.550 442.525 ;
        RECT 216.390 438.495 218.770 442.525 ;
        RECT 219.610 438.495 221.990 442.525 ;
        RECT 222.830 438.495 225.210 442.525 ;
        RECT 226.050 438.495 228.430 442.525 ;
        RECT 229.270 438.495 231.650 442.525 ;
        RECT 232.490 438.495 234.870 442.525 ;
        RECT 235.710 438.495 238.090 442.525 ;
        RECT 238.930 438.495 241.310 442.525 ;
        RECT 242.150 438.495 244.530 442.525 ;
        RECT 245.370 438.495 247.750 442.525 ;
        RECT 248.590 438.495 250.970 442.525 ;
        RECT 251.810 438.495 254.190 442.525 ;
        RECT 255.030 438.495 257.410 442.525 ;
        RECT 258.250 438.495 260.630 442.525 ;
        RECT 261.470 438.495 263.850 442.525 ;
        RECT 264.690 438.495 267.070 442.525 ;
        RECT 267.910 438.495 270.290 442.525 ;
        RECT 271.130 438.495 273.510 442.525 ;
        RECT 274.350 438.495 276.730 442.525 ;
        RECT 277.570 438.495 279.950 442.525 ;
        RECT 280.790 438.495 283.170 442.525 ;
        RECT 284.010 438.495 286.390 442.525 ;
        RECT 287.230 438.495 289.610 442.525 ;
        RECT 290.450 438.495 292.830 442.525 ;
        RECT 293.670 438.495 296.050 442.525 ;
        RECT 296.890 438.495 299.270 442.525 ;
        RECT 300.110 438.495 302.490 442.525 ;
        RECT 303.330 438.495 308.930 442.525 ;
        RECT 309.770 438.495 334.690 442.525 ;
        RECT 335.530 438.495 337.910 442.525 ;
        RECT 338.750 438.495 341.130 442.525 ;
        RECT 341.970 438.495 344.350 442.525 ;
        RECT 345.190 438.495 347.570 442.525 ;
        RECT 348.410 438.495 350.790 442.525 ;
        RECT 351.630 438.495 357.230 442.525 ;
        RECT 358.070 438.495 360.450 442.525 ;
        RECT 361.290 438.495 363.670 442.525 ;
        RECT 364.510 438.495 366.890 442.525 ;
        RECT 367.730 438.495 370.110 442.525 ;
        RECT 370.950 438.495 373.330 442.525 ;
        RECT 374.170 438.495 376.550 442.525 ;
        RECT 377.390 438.495 379.770 442.525 ;
        RECT 380.610 438.495 382.990 442.525 ;
        RECT 383.830 438.495 386.210 442.525 ;
        RECT 387.050 438.495 389.430 442.525 ;
        RECT 390.270 438.495 392.650 442.525 ;
        RECT 393.490 438.495 395.870 442.525 ;
        RECT 396.710 438.495 399.090 442.525 ;
        RECT 399.930 438.495 402.310 442.525 ;
        RECT 403.150 438.495 405.530 442.525 ;
        RECT 406.370 438.495 408.750 442.525 ;
        RECT 409.590 438.495 411.970 442.525 ;
        RECT 412.810 438.495 415.190 442.525 ;
        RECT 416.030 438.495 418.410 442.525 ;
        RECT 419.250 438.495 421.630 442.525 ;
        RECT 422.470 438.495 424.850 442.525 ;
        RECT 425.690 438.495 428.070 442.525 ;
        RECT 4.230 4.280 428.620 438.495 ;
        RECT 4.230 0.155 6.250 4.280 ;
        RECT 7.090 0.155 9.470 4.280 ;
        RECT 10.310 0.155 12.690 4.280 ;
        RECT 13.530 0.155 15.910 4.280 ;
        RECT 16.750 0.155 19.130 4.280 ;
        RECT 19.970 0.155 22.350 4.280 ;
        RECT 23.190 0.155 25.570 4.280 ;
        RECT 26.410 0.155 28.790 4.280 ;
        RECT 29.630 0.155 32.010 4.280 ;
        RECT 32.850 0.155 35.230 4.280 ;
        RECT 36.070 0.155 38.450 4.280 ;
        RECT 39.290 0.155 41.670 4.280 ;
        RECT 42.510 0.155 44.890 4.280 ;
        RECT 45.730 0.155 48.110 4.280 ;
        RECT 48.950 0.155 51.330 4.280 ;
        RECT 52.170 0.155 54.550 4.280 ;
        RECT 55.390 0.155 57.770 4.280 ;
        RECT 58.610 0.155 60.990 4.280 ;
        RECT 61.830 0.155 64.210 4.280 ;
        RECT 65.050 0.155 67.430 4.280 ;
        RECT 68.270 0.155 70.650 4.280 ;
        RECT 71.490 0.155 73.870 4.280 ;
        RECT 74.710 0.155 77.090 4.280 ;
        RECT 77.930 0.155 80.310 4.280 ;
        RECT 81.150 0.155 83.530 4.280 ;
        RECT 84.370 0.155 86.750 4.280 ;
        RECT 87.590 0.155 89.970 4.280 ;
        RECT 90.810 0.155 93.190 4.280 ;
        RECT 94.030 0.155 96.410 4.280 ;
        RECT 97.250 0.155 99.630 4.280 ;
        RECT 100.470 0.155 102.850 4.280 ;
        RECT 103.690 0.155 106.070 4.280 ;
        RECT 106.910 0.155 109.290 4.280 ;
        RECT 110.130 0.155 112.510 4.280 ;
        RECT 113.350 0.155 115.730 4.280 ;
        RECT 116.570 0.155 118.950 4.280 ;
        RECT 119.790 0.155 122.170 4.280 ;
        RECT 123.010 0.155 125.390 4.280 ;
        RECT 126.230 0.155 128.610 4.280 ;
        RECT 129.450 0.155 131.830 4.280 ;
        RECT 132.670 0.155 135.050 4.280 ;
        RECT 135.890 0.155 138.270 4.280 ;
        RECT 139.110 0.155 141.490 4.280 ;
        RECT 142.330 0.155 144.710 4.280 ;
        RECT 145.550 0.155 147.930 4.280 ;
        RECT 148.770 0.155 151.150 4.280 ;
        RECT 151.990 0.155 154.370 4.280 ;
        RECT 155.210 0.155 157.590 4.280 ;
        RECT 158.430 0.155 160.810 4.280 ;
        RECT 161.650 0.155 164.030 4.280 ;
        RECT 164.870 0.155 167.250 4.280 ;
        RECT 168.090 0.155 170.470 4.280 ;
        RECT 171.310 0.155 173.690 4.280 ;
        RECT 174.530 0.155 176.910 4.280 ;
        RECT 177.750 0.155 180.130 4.280 ;
        RECT 180.970 0.155 183.350 4.280 ;
        RECT 184.190 0.155 186.570 4.280 ;
        RECT 187.410 0.155 189.790 4.280 ;
        RECT 190.630 0.155 193.010 4.280 ;
        RECT 193.850 0.155 196.230 4.280 ;
        RECT 197.070 0.155 199.450 4.280 ;
        RECT 200.290 0.155 202.670 4.280 ;
        RECT 203.510 0.155 205.890 4.280 ;
        RECT 206.730 0.155 209.110 4.280 ;
        RECT 209.950 0.155 212.330 4.280 ;
        RECT 213.170 0.155 215.550 4.280 ;
        RECT 216.390 0.155 218.770 4.280 ;
        RECT 219.610 0.155 221.990 4.280 ;
        RECT 222.830 0.155 225.210 4.280 ;
        RECT 226.050 0.155 228.430 4.280 ;
        RECT 229.270 0.155 231.650 4.280 ;
        RECT 232.490 0.155 234.870 4.280 ;
        RECT 235.710 0.155 238.090 4.280 ;
        RECT 238.930 0.155 241.310 4.280 ;
        RECT 242.150 0.155 244.530 4.280 ;
        RECT 245.370 0.155 247.750 4.280 ;
        RECT 248.590 0.155 250.970 4.280 ;
        RECT 251.810 0.155 254.190 4.280 ;
        RECT 255.030 0.155 257.410 4.280 ;
        RECT 258.250 0.155 260.630 4.280 ;
        RECT 261.470 0.155 263.850 4.280 ;
        RECT 264.690 0.155 267.070 4.280 ;
        RECT 267.910 0.155 270.290 4.280 ;
        RECT 271.130 0.155 273.510 4.280 ;
        RECT 274.350 0.155 276.730 4.280 ;
        RECT 277.570 0.155 279.950 4.280 ;
        RECT 280.790 0.155 283.170 4.280 ;
        RECT 284.010 0.155 286.390 4.280 ;
        RECT 287.230 0.155 289.610 4.280 ;
        RECT 290.450 0.155 292.830 4.280 ;
        RECT 293.670 0.155 296.050 4.280 ;
        RECT 296.890 0.155 299.270 4.280 ;
        RECT 300.110 0.155 302.490 4.280 ;
        RECT 303.330 0.155 305.710 4.280 ;
        RECT 306.550 0.155 308.930 4.280 ;
        RECT 309.770 0.155 312.150 4.280 ;
        RECT 312.990 0.155 315.370 4.280 ;
        RECT 316.210 0.155 318.590 4.280 ;
        RECT 319.430 0.155 321.810 4.280 ;
        RECT 322.650 0.155 325.030 4.280 ;
        RECT 325.870 0.155 328.250 4.280 ;
        RECT 329.090 0.155 331.470 4.280 ;
        RECT 332.310 0.155 334.690 4.280 ;
        RECT 335.530 0.155 337.910 4.280 ;
        RECT 338.750 0.155 341.130 4.280 ;
        RECT 341.970 0.155 344.350 4.280 ;
        RECT 345.190 0.155 347.570 4.280 ;
        RECT 348.410 0.155 350.790 4.280 ;
        RECT 351.630 0.155 354.010 4.280 ;
        RECT 354.850 0.155 357.230 4.280 ;
        RECT 358.070 0.155 360.450 4.280 ;
        RECT 361.290 0.155 363.670 4.280 ;
        RECT 364.510 0.155 366.890 4.280 ;
        RECT 367.730 0.155 370.110 4.280 ;
        RECT 370.950 0.155 373.330 4.280 ;
        RECT 374.170 0.155 376.550 4.280 ;
        RECT 377.390 0.155 379.770 4.280 ;
        RECT 380.610 0.155 382.990 4.280 ;
        RECT 383.830 0.155 386.210 4.280 ;
        RECT 387.050 0.155 389.430 4.280 ;
        RECT 390.270 0.155 392.650 4.280 ;
        RECT 393.490 0.155 395.870 4.280 ;
        RECT 396.710 0.155 399.090 4.280 ;
        RECT 399.930 0.155 402.310 4.280 ;
        RECT 403.150 0.155 405.530 4.280 ;
        RECT 406.370 0.155 408.750 4.280 ;
        RECT 409.590 0.155 411.970 4.280 ;
        RECT 412.810 0.155 415.190 4.280 ;
        RECT 416.030 0.155 418.410 4.280 ;
        RECT 419.250 0.155 421.630 4.280 ;
        RECT 422.470 0.155 424.850 4.280 ;
        RECT 425.690 0.155 428.070 4.280 ;
      LAYER met3 ;
        RECT 3.750 441.640 427.655 442.505 ;
        RECT 3.750 439.640 428.055 441.640 ;
        RECT 3.750 438.240 427.655 439.640 ;
        RECT 3.750 436.240 428.055 438.240 ;
        RECT 3.750 434.840 427.655 436.240 ;
        RECT 3.750 432.840 428.055 434.840 ;
        RECT 3.750 431.440 427.655 432.840 ;
        RECT 3.750 429.440 428.055 431.440 ;
        RECT 3.750 428.040 427.655 429.440 ;
        RECT 3.750 426.040 428.055 428.040 ;
        RECT 3.750 424.640 427.655 426.040 ;
        RECT 3.750 422.640 428.055 424.640 ;
        RECT 3.750 421.240 427.655 422.640 ;
        RECT 3.750 419.240 428.055 421.240 ;
        RECT 3.750 417.840 427.655 419.240 ;
        RECT 3.750 415.840 428.055 417.840 ;
        RECT 3.750 414.440 427.655 415.840 ;
        RECT 3.750 412.440 428.055 414.440 ;
        RECT 3.750 411.040 427.655 412.440 ;
        RECT 3.750 409.040 428.055 411.040 ;
        RECT 3.750 407.640 427.655 409.040 ;
        RECT 3.750 405.640 428.055 407.640 ;
        RECT 3.750 404.240 427.655 405.640 ;
        RECT 3.750 402.240 428.055 404.240 ;
        RECT 3.750 400.840 427.655 402.240 ;
        RECT 3.750 398.840 428.055 400.840 ;
        RECT 3.750 397.440 427.655 398.840 ;
        RECT 3.750 395.440 428.055 397.440 ;
        RECT 3.750 394.040 427.655 395.440 ;
        RECT 3.750 392.040 428.055 394.040 ;
        RECT 3.750 390.640 427.655 392.040 ;
        RECT 3.750 388.640 428.055 390.640 ;
        RECT 3.750 387.240 427.655 388.640 ;
        RECT 3.750 385.240 428.055 387.240 ;
        RECT 3.750 383.840 427.655 385.240 ;
        RECT 3.750 381.840 428.055 383.840 ;
        RECT 3.750 380.440 427.655 381.840 ;
        RECT 3.750 378.440 428.055 380.440 ;
        RECT 3.750 377.040 427.655 378.440 ;
        RECT 3.750 375.040 428.055 377.040 ;
        RECT 3.750 373.640 427.655 375.040 ;
        RECT 3.750 371.640 428.055 373.640 ;
        RECT 3.750 370.240 427.655 371.640 ;
        RECT 3.750 368.240 428.055 370.240 ;
        RECT 3.750 366.840 427.655 368.240 ;
        RECT 3.750 364.840 428.055 366.840 ;
        RECT 3.750 363.440 427.655 364.840 ;
        RECT 3.750 361.440 428.055 363.440 ;
        RECT 3.750 360.040 427.655 361.440 ;
        RECT 3.750 358.040 428.055 360.040 ;
        RECT 3.750 356.640 427.655 358.040 ;
        RECT 3.750 354.640 428.055 356.640 ;
        RECT 3.750 353.240 427.655 354.640 ;
        RECT 3.750 351.240 428.055 353.240 ;
        RECT 3.750 349.840 427.655 351.240 ;
        RECT 3.750 347.840 428.055 349.840 ;
        RECT 3.750 346.440 427.655 347.840 ;
        RECT 3.750 344.440 428.055 346.440 ;
        RECT 3.750 343.040 427.655 344.440 ;
        RECT 3.750 341.040 428.055 343.040 ;
        RECT 3.750 339.640 427.655 341.040 ;
        RECT 3.750 337.640 428.055 339.640 ;
        RECT 4.400 336.240 427.655 337.640 ;
        RECT 3.750 334.240 428.055 336.240 ;
        RECT 4.400 332.840 427.655 334.240 ;
        RECT 3.750 330.840 428.055 332.840 ;
        RECT 4.400 329.440 427.655 330.840 ;
        RECT 3.750 327.440 428.055 329.440 ;
        RECT 4.400 326.040 427.655 327.440 ;
        RECT 3.750 324.040 428.055 326.040 ;
        RECT 4.400 322.640 427.655 324.040 ;
        RECT 3.750 320.640 428.055 322.640 ;
        RECT 4.400 319.240 427.655 320.640 ;
        RECT 3.750 317.240 428.055 319.240 ;
        RECT 4.400 315.840 427.655 317.240 ;
        RECT 3.750 313.840 428.055 315.840 ;
        RECT 4.400 312.440 427.655 313.840 ;
        RECT 3.750 310.440 428.055 312.440 ;
        RECT 4.400 309.040 427.655 310.440 ;
        RECT 3.750 307.040 428.055 309.040 ;
        RECT 4.400 305.640 427.655 307.040 ;
        RECT 3.750 303.640 428.055 305.640 ;
        RECT 4.400 302.240 427.655 303.640 ;
        RECT 3.750 300.240 428.055 302.240 ;
        RECT 4.400 298.840 427.655 300.240 ;
        RECT 3.750 296.840 428.055 298.840 ;
        RECT 4.400 295.440 427.655 296.840 ;
        RECT 3.750 293.440 428.055 295.440 ;
        RECT 4.400 292.040 427.655 293.440 ;
        RECT 3.750 290.040 428.055 292.040 ;
        RECT 4.400 288.640 427.655 290.040 ;
        RECT 3.750 286.640 428.055 288.640 ;
        RECT 4.400 285.240 427.655 286.640 ;
        RECT 3.750 283.240 428.055 285.240 ;
        RECT 4.400 281.840 427.655 283.240 ;
        RECT 3.750 279.840 428.055 281.840 ;
        RECT 4.400 278.440 427.655 279.840 ;
        RECT 3.750 276.440 428.055 278.440 ;
        RECT 4.400 275.040 427.655 276.440 ;
        RECT 3.750 273.040 428.055 275.040 ;
        RECT 4.400 271.640 427.655 273.040 ;
        RECT 3.750 269.640 428.055 271.640 ;
        RECT 4.400 268.240 427.655 269.640 ;
        RECT 3.750 266.240 428.055 268.240 ;
        RECT 4.400 264.840 427.655 266.240 ;
        RECT 3.750 262.840 428.055 264.840 ;
        RECT 4.400 261.440 427.655 262.840 ;
        RECT 3.750 259.440 428.055 261.440 ;
        RECT 4.400 258.040 427.655 259.440 ;
        RECT 3.750 256.040 428.055 258.040 ;
        RECT 4.400 254.640 427.655 256.040 ;
        RECT 3.750 252.640 428.055 254.640 ;
        RECT 4.400 251.240 427.655 252.640 ;
        RECT 3.750 249.240 428.055 251.240 ;
        RECT 4.400 247.840 427.655 249.240 ;
        RECT 3.750 245.840 428.055 247.840 ;
        RECT 4.400 244.440 427.655 245.840 ;
        RECT 3.750 242.440 428.055 244.440 ;
        RECT 4.400 241.040 427.655 242.440 ;
        RECT 3.750 239.040 428.055 241.040 ;
        RECT 4.400 237.640 427.655 239.040 ;
        RECT 3.750 235.640 428.055 237.640 ;
        RECT 4.400 234.240 427.655 235.640 ;
        RECT 3.750 232.240 428.055 234.240 ;
        RECT 4.400 230.840 427.655 232.240 ;
        RECT 3.750 228.840 428.055 230.840 ;
        RECT 4.400 227.440 427.655 228.840 ;
        RECT 3.750 225.440 428.055 227.440 ;
        RECT 4.400 224.040 427.655 225.440 ;
        RECT 3.750 222.040 428.055 224.040 ;
        RECT 4.400 220.640 427.655 222.040 ;
        RECT 3.750 218.640 428.055 220.640 ;
        RECT 4.400 217.240 427.655 218.640 ;
        RECT 3.750 215.240 428.055 217.240 ;
        RECT 4.400 213.840 427.655 215.240 ;
        RECT 3.750 211.840 428.055 213.840 ;
        RECT 4.400 210.440 427.655 211.840 ;
        RECT 3.750 208.440 428.055 210.440 ;
        RECT 4.400 207.040 427.655 208.440 ;
        RECT 3.750 205.040 428.055 207.040 ;
        RECT 4.400 203.640 427.655 205.040 ;
        RECT 3.750 201.640 428.055 203.640 ;
        RECT 4.400 200.240 427.655 201.640 ;
        RECT 3.750 198.240 428.055 200.240 ;
        RECT 4.400 196.840 427.655 198.240 ;
        RECT 3.750 194.840 428.055 196.840 ;
        RECT 4.400 193.440 427.655 194.840 ;
        RECT 3.750 191.440 428.055 193.440 ;
        RECT 4.400 190.040 427.655 191.440 ;
        RECT 3.750 188.040 428.055 190.040 ;
        RECT 4.400 186.640 427.655 188.040 ;
        RECT 3.750 184.640 428.055 186.640 ;
        RECT 4.400 183.240 427.655 184.640 ;
        RECT 3.750 181.240 428.055 183.240 ;
        RECT 4.400 179.840 427.655 181.240 ;
        RECT 3.750 177.840 428.055 179.840 ;
        RECT 4.400 176.440 427.655 177.840 ;
        RECT 3.750 174.440 428.055 176.440 ;
        RECT 4.400 173.040 427.655 174.440 ;
        RECT 3.750 171.040 428.055 173.040 ;
        RECT 4.400 169.640 427.655 171.040 ;
        RECT 3.750 167.640 428.055 169.640 ;
        RECT 4.400 166.240 427.655 167.640 ;
        RECT 3.750 164.240 428.055 166.240 ;
        RECT 4.400 162.840 427.655 164.240 ;
        RECT 3.750 160.840 428.055 162.840 ;
        RECT 4.400 159.440 427.655 160.840 ;
        RECT 3.750 157.440 428.055 159.440 ;
        RECT 4.400 156.040 427.655 157.440 ;
        RECT 3.750 154.040 428.055 156.040 ;
        RECT 4.400 152.640 427.655 154.040 ;
        RECT 3.750 150.640 428.055 152.640 ;
        RECT 4.400 149.240 427.655 150.640 ;
        RECT 3.750 147.240 428.055 149.240 ;
        RECT 4.400 145.840 427.655 147.240 ;
        RECT 3.750 143.840 428.055 145.840 ;
        RECT 4.400 142.440 427.655 143.840 ;
        RECT 3.750 140.440 428.055 142.440 ;
        RECT 4.400 139.040 427.655 140.440 ;
        RECT 3.750 137.040 428.055 139.040 ;
        RECT 4.400 135.640 427.655 137.040 ;
        RECT 3.750 133.640 428.055 135.640 ;
        RECT 4.400 132.240 427.655 133.640 ;
        RECT 3.750 130.240 428.055 132.240 ;
        RECT 4.400 128.840 427.655 130.240 ;
        RECT 3.750 126.840 428.055 128.840 ;
        RECT 4.400 125.440 427.655 126.840 ;
        RECT 3.750 123.440 428.055 125.440 ;
        RECT 4.400 122.040 427.655 123.440 ;
        RECT 3.750 120.040 428.055 122.040 ;
        RECT 4.400 118.640 427.655 120.040 ;
        RECT 3.750 116.640 428.055 118.640 ;
        RECT 3.750 115.240 427.655 116.640 ;
        RECT 3.750 113.240 428.055 115.240 ;
        RECT 3.750 111.840 427.655 113.240 ;
        RECT 3.750 109.840 428.055 111.840 ;
        RECT 3.750 108.440 427.655 109.840 ;
        RECT 3.750 106.440 428.055 108.440 ;
        RECT 3.750 105.040 427.655 106.440 ;
        RECT 3.750 103.040 428.055 105.040 ;
        RECT 3.750 101.640 427.655 103.040 ;
        RECT 3.750 99.640 428.055 101.640 ;
        RECT 3.750 98.240 427.655 99.640 ;
        RECT 3.750 96.240 428.055 98.240 ;
        RECT 3.750 94.840 427.655 96.240 ;
        RECT 3.750 92.840 428.055 94.840 ;
        RECT 3.750 91.440 427.655 92.840 ;
        RECT 3.750 89.440 428.055 91.440 ;
        RECT 3.750 88.040 427.655 89.440 ;
        RECT 3.750 86.040 428.055 88.040 ;
        RECT 3.750 84.640 427.655 86.040 ;
        RECT 3.750 82.640 428.055 84.640 ;
        RECT 3.750 81.240 427.655 82.640 ;
        RECT 3.750 79.240 428.055 81.240 ;
        RECT 3.750 77.840 427.655 79.240 ;
        RECT 3.750 75.840 428.055 77.840 ;
        RECT 3.750 74.440 427.655 75.840 ;
        RECT 3.750 72.440 428.055 74.440 ;
        RECT 3.750 71.040 427.655 72.440 ;
        RECT 3.750 69.040 428.055 71.040 ;
        RECT 3.750 67.640 427.655 69.040 ;
        RECT 3.750 65.640 428.055 67.640 ;
        RECT 3.750 64.240 427.655 65.640 ;
        RECT 3.750 62.240 428.055 64.240 ;
        RECT 3.750 60.840 427.655 62.240 ;
        RECT 3.750 58.840 428.055 60.840 ;
        RECT 3.750 57.440 427.655 58.840 ;
        RECT 3.750 55.440 428.055 57.440 ;
        RECT 3.750 54.040 427.655 55.440 ;
        RECT 3.750 52.040 428.055 54.040 ;
        RECT 3.750 50.640 427.655 52.040 ;
        RECT 3.750 48.640 428.055 50.640 ;
        RECT 3.750 47.240 427.655 48.640 ;
        RECT 3.750 45.240 428.055 47.240 ;
        RECT 3.750 43.840 427.655 45.240 ;
        RECT 3.750 41.840 428.055 43.840 ;
        RECT 3.750 40.440 427.655 41.840 ;
        RECT 3.750 38.440 428.055 40.440 ;
        RECT 3.750 37.040 427.655 38.440 ;
        RECT 3.750 35.040 428.055 37.040 ;
        RECT 3.750 33.640 427.655 35.040 ;
        RECT 3.750 31.640 428.055 33.640 ;
        RECT 3.750 30.240 427.655 31.640 ;
        RECT 3.750 28.240 428.055 30.240 ;
        RECT 3.750 26.840 427.655 28.240 ;
        RECT 3.750 24.840 428.055 26.840 ;
        RECT 3.750 23.440 427.655 24.840 ;
        RECT 3.750 21.440 428.055 23.440 ;
        RECT 3.750 20.040 427.655 21.440 ;
        RECT 3.750 18.040 428.055 20.040 ;
        RECT 3.750 16.640 427.655 18.040 ;
        RECT 3.750 14.640 428.055 16.640 ;
        RECT 3.750 13.240 427.655 14.640 ;
        RECT 3.750 11.240 428.055 13.240 ;
        RECT 3.750 9.840 427.655 11.240 ;
        RECT 3.750 7.840 428.055 9.840 ;
        RECT 3.750 6.440 427.655 7.840 ;
        RECT 3.750 4.440 428.055 6.440 ;
        RECT 3.750 3.040 427.655 4.440 ;
        RECT 3.750 1.040 428.055 3.040 ;
        RECT 3.750 0.175 427.655 1.040 ;
      LAYER met4 ;
        RECT 3.975 17.855 20.640 428.225 ;
        RECT 23.040 17.855 23.940 428.225 ;
        RECT 26.340 17.855 174.240 428.225 ;
        RECT 176.640 17.855 177.540 428.225 ;
        RECT 179.940 17.855 327.840 428.225 ;
        RECT 330.240 17.855 331.140 428.225 ;
        RECT 333.540 17.855 420.145 428.225 ;
  END
END picorv32
END LIBRARY

